VERSION 5.7 ;
BUSBITCHARS "[]" ;
DIVIDERCHAR "/" ;

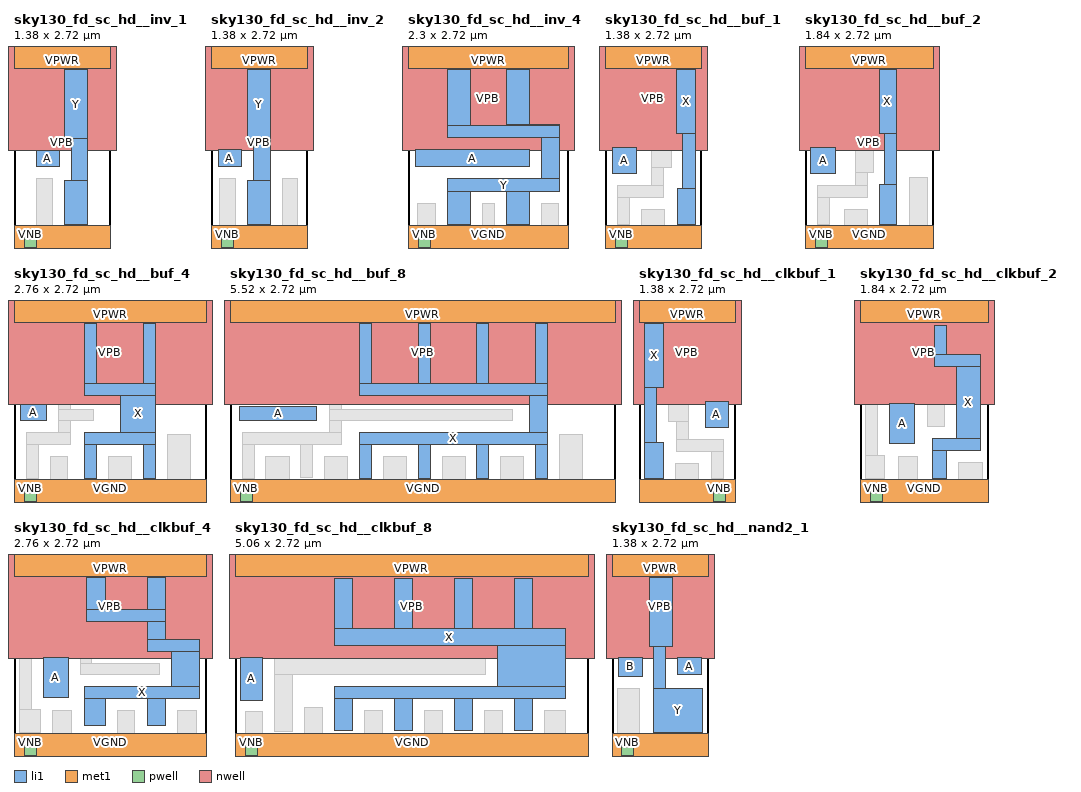
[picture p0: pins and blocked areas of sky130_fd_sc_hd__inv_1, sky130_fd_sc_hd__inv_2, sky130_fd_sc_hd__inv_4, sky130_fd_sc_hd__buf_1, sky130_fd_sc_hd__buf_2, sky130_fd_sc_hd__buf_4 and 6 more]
MACRO sky130_fd_sc_hd__inv_1
  CLASS CORE ;
  FOREIGN sky130_fd_sc_hd__inv_1 ;
  ORIGIN  0.000000  0.000000 ;
  SIZE  1.380000 BY  2.720000 ;
  SYMMETRY X Y R90 ;
  SITE unithd ;
  PIN A
    ANTENNAGATEAREA  0.247500 ;
    DIRECTION INPUT ;
    USE SIGNAL ;
    PORT
      LAYER li1 ;
        RECT 0.320000 1.075000 0.650000 1.315000 ;
    END
  END A
  PIN Y
    ANTENNADIFFAREA  0.429000 ;
    DIRECTION OUTPUT ;
    USE SIGNAL ;
    PORT
      LAYER li1 ;
        RECT 0.720000 0.255000 1.050000 0.885000 ;
        RECT 0.720000 1.485000 1.050000 2.465000 ;
        RECT 0.820000 0.885000 1.050000 1.485000 ;
    END
  END Y
  PIN VGND
    DIRECTION INOUT ;
    SHAPE ABUTMENT ;
    USE GROUND ;
    PORT
      LAYER met1 ;
        RECT 0.000000 -0.240000 1.380000 0.240000 ;
    END
  END VGND
  PIN VNB
    DIRECTION INOUT ;
    USE GROUND ;
    PORT
      LAYER pwell ;
        RECT 0.145000 -0.085000 0.315000 0.085000 ;
    END
  END VNB
  PIN VPB
    DIRECTION INOUT ;
    USE POWER ;
    PORT
      LAYER nwell ;
        RECT -0.190000 1.305000 1.570000 2.910000 ;
    END
  END VPB
  PIN VPWR
    DIRECTION INOUT ;
    SHAPE ABUTMENT ;
    USE POWER ;
    PORT
      LAYER met1 ;
        RECT 0.000000 2.480000 1.380000 2.960000 ;
    END
  END VPWR
  OBS
    LAYER li1 ;
      RECT 0.000000 -0.085000 1.380000 0.085000 ;
      RECT 0.000000  2.635000 1.380000 2.805000 ;
      RECT 0.320000  0.085000 0.550000 0.905000 ;
      RECT 0.340000  1.495000 0.550000 2.635000 ;
    LAYER mcon ;
      RECT 0.145000 -0.085000 0.315000 0.085000 ;
      RECT 0.145000  2.635000 0.315000 2.805000 ;
      RECT 0.605000 -0.085000 0.775000 0.085000 ;
      RECT 0.605000  2.635000 0.775000 2.805000 ;
      RECT 1.065000 -0.085000 1.235000 0.085000 ;
      RECT 1.065000  2.635000 1.235000 2.805000 ;
  END
END sky130_fd_sc_hd__inv_1

MACRO sky130_fd_sc_hd__inv_2
  CLASS CORE ;
  FOREIGN sky130_fd_sc_hd__inv_2 ;
  ORIGIN  0.000000  0.000000 ;
  SIZE  1.380000 BY  2.720000 ;
  SYMMETRY X Y R90 ;
  SITE unithd ;
  PIN A
    ANTENNAGATEAREA  0.495000 ;
    DIRECTION INPUT ;
    USE SIGNAL ;
    PORT
      LAYER li1 ;
        RECT 0.105000 1.075000 0.435000 1.325000 ;
    END
  END A
  PIN Y
    ANTENNADIFFAREA  0.445500 ;
    DIRECTION OUTPUT ;
    USE SIGNAL ;
    PORT
      LAYER li1 ;
        RECT 0.525000 0.255000 0.855000 0.885000 ;
        RECT 0.525000 1.485000 0.855000 2.465000 ;
        RECT 0.605000 0.885000 0.855000 1.485000 ;
    END
  END Y
  PIN VGND
    DIRECTION INOUT ;
    SHAPE ABUTMENT ;
    USE GROUND ;
    PORT
      LAYER met1 ;
        RECT 0.000000 -0.240000 1.380000 0.240000 ;
    END
  END VGND
  PIN VNB
    DIRECTION INOUT ;
    USE GROUND ;
    PORT
      LAYER pwell ;
        RECT 0.145000 -0.085000 0.315000 0.085000 ;
    END
  END VNB
  PIN VPB
    DIRECTION INOUT ;
    USE POWER ;
    PORT
      LAYER nwell ;
        RECT -0.190000 1.305000 1.570000 2.910000 ;
    END
  END VPB
  PIN VPWR
    DIRECTION INOUT ;
    SHAPE ABUTMENT ;
    USE POWER ;
    PORT
      LAYER met1 ;
        RECT 0.000000 2.480000 1.380000 2.960000 ;
    END
  END VPWR
  OBS
    LAYER li1 ;
      RECT 0.000000 -0.085000 1.380000 0.085000 ;
      RECT 0.000000  2.635000 1.380000 2.805000 ;
      RECT 0.125000  0.085000 0.355000 0.905000 ;
      RECT 0.125000  1.495000 0.355000 2.635000 ;
      RECT 1.025000  0.085000 1.235000 0.905000 ;
      RECT 1.025000  1.495000 1.235000 2.635000 ;
    LAYER mcon ;
      RECT 0.145000 -0.085000 0.315000 0.085000 ;
      RECT 0.145000  2.635000 0.315000 2.805000 ;
      RECT 0.605000 -0.085000 0.775000 0.085000 ;
      RECT 0.605000  2.635000 0.775000 2.805000 ;
      RECT 1.065000 -0.085000 1.235000 0.085000 ;
      RECT 1.065000  2.635000 1.235000 2.805000 ;
  END
END sky130_fd_sc_hd__inv_2

MACRO sky130_fd_sc_hd__inv_4
  CLASS CORE ;
  FOREIGN sky130_fd_sc_hd__inv_4 ;
  ORIGIN  0.000000  0.000000 ;
  SIZE  2.300000 BY  2.720000 ;
  SYMMETRY X Y R90 ;
  SITE unithd ;
  PIN A
    ANTENNAGATEAREA  0.990000 ;
    DIRECTION INPUT ;
    USE SIGNAL ;
    PORT
      LAYER li1 ;
        RECT 0.105000 1.075000 1.735000 1.325000 ;
    END
  END A
  PIN Y
    ANTENNADIFFAREA  0.891000 ;
    DIRECTION OUTPUT ;
    USE SIGNAL ;
    PORT
      LAYER li1 ;
        RECT 0.565000 0.255000 0.895000 0.725000 ;
        RECT 0.565000 0.725000 2.170000 0.905000 ;
        RECT 0.565000 1.495000 2.170000 1.665000 ;
        RECT 0.565000 1.665000 0.895000 2.465000 ;
        RECT 1.405000 0.255000 1.735000 0.725000 ;
        RECT 1.405000 1.665000 2.170000 1.685000 ;
        RECT 1.405000 1.685000 1.735000 2.465000 ;
        RECT 1.905000 0.905000 2.170000 1.495000 ;
    END
  END Y
  PIN VGND
    DIRECTION INOUT ;
    SHAPE ABUTMENT ;
    USE GROUND ;
    PORT
      LAYER met1 ;
        RECT 0.000000 -0.240000 2.300000 0.240000 ;
    END
  END VGND
  PIN VNB
    DIRECTION INOUT ;
    USE GROUND ;
    PORT
      LAYER pwell ;
        RECT 0.145000 -0.085000 0.315000 0.085000 ;
    END
  END VNB
  PIN VPB
    DIRECTION INOUT ;
    USE POWER ;
    PORT
      LAYER nwell ;
        RECT -0.190000 1.305000 2.490000 2.910000 ;
    END
  END VPB
  PIN VPWR
    DIRECTION INOUT ;
    SHAPE ABUTMENT ;
    USE POWER ;
    PORT
      LAYER met1 ;
        RECT 0.000000 2.480000 2.300000 2.960000 ;
    END
  END VPWR
  OBS
    LAYER li1 ;
      RECT 0.000000 -0.085000 2.300000 0.085000 ;
      RECT 0.000000  2.635000 2.300000 2.805000 ;
      RECT 0.130000  0.085000 0.395000 0.545000 ;
      RECT 0.130000  1.495000 0.395000 2.635000 ;
      RECT 1.065000  0.085000 1.235000 0.545000 ;
      RECT 1.065000  1.835000 1.235000 2.635000 ;
      RECT 1.905000  0.085000 2.155000 0.550000 ;
      RECT 1.905000  2.175000 2.115000 2.635000 ;
    LAYER mcon ;
      RECT 0.145000 -0.085000 0.315000 0.085000 ;
      RECT 0.145000  2.635000 0.315000 2.805000 ;
      RECT 0.605000 -0.085000 0.775000 0.085000 ;
      RECT 0.605000  2.635000 0.775000 2.805000 ;
      RECT 1.065000 -0.085000 1.235000 0.085000 ;
      RECT 1.065000  2.635000 1.235000 2.805000 ;
      RECT 1.525000 -0.085000 1.695000 0.085000 ;
      RECT 1.525000  2.635000 1.695000 2.805000 ;
      RECT 1.985000 -0.085000 2.155000 0.085000 ;
      RECT 1.985000  2.635000 2.155000 2.805000 ;
  END
END sky130_fd_sc_hd__inv_4

MACRO sky130_fd_sc_hd__buf_1
  CLASS CORE ;
  FOREIGN sky130_fd_sc_hd__buf_1 ;
  ORIGIN  0.000000  0.000000 ;
  SIZE  1.380000 BY  2.720000 ;
  SYMMETRY X Y R90 ;
  SITE unithd ;
  PIN A
    ANTENNAGATEAREA  0.196500 ;
    DIRECTION INPUT ;
    USE SIGNAL ;
    PORT
      LAYER li1 ;
        RECT 0.105000 0.985000 0.445000 1.355000 ;
    END
  END A
  PIN X
    ANTENNADIFFAREA  0.340600 ;
    DIRECTION OUTPUT ;
    USE SIGNAL ;
    PORT
      LAYER li1 ;
        RECT 1.025000 1.560000 1.295000 2.465000 ;
        RECT 1.035000 0.255000 1.295000 0.760000 ;
        RECT 1.115000 0.760000 1.295000 1.560000 ;
    END
  END X
  PIN VGND
    DIRECTION INOUT ;
    SHAPE ABUTMENT ;
    USE GROUND ;
    PORT
      LAYER met1 ;
        RECT 0.000000 -0.240000 1.380000 0.240000 ;
    END
  END VGND
  PIN VNB
    DIRECTION INOUT ;
    USE GROUND ;
    PORT
      LAYER pwell ;
        RECT 0.155000 -0.085000 0.325000 0.085000 ;
    END
  END VNB
  PIN VPB
    DIRECTION INOUT ;
    USE POWER ;
    PORT
      LAYER nwell ;
        RECT -0.190000 1.305000 1.570000 2.910000 ;
    END
  END VPB
  PIN VPWR
    DIRECTION INOUT ;
    SHAPE ABUTMENT ;
    USE POWER ;
    PORT
      LAYER met1 ;
        RECT 0.000000 2.480000 1.380000 2.960000 ;
    END
  END VPWR
  OBS
    LAYER li1 ;
      RECT 0.000000 -0.085000 1.380000 0.085000 ;
      RECT 0.000000  2.635000 1.380000 2.805000 ;
      RECT 0.165000  1.535000 0.840000 1.705000 ;
      RECT 0.165000  1.705000 0.345000 2.465000 ;
      RECT 0.175000  0.255000 0.345000 0.635000 ;
      RECT 0.175000  0.635000 0.840000 0.805000 ;
      RECT 0.525000  0.085000 0.855000 0.465000 ;
      RECT 0.525000  1.875000 0.855000 2.635000 ;
      RECT 0.670000  0.805000 0.840000 1.060000 ;
      RECT 0.670000  1.060000 0.945000 1.390000 ;
      RECT 0.670000  1.390000 0.840000 1.535000 ;
    LAYER mcon ;
      RECT 0.145000 -0.085000 0.315000 0.085000 ;
      RECT 0.145000  2.635000 0.315000 2.805000 ;
      RECT 0.605000 -0.085000 0.775000 0.085000 ;
      RECT 0.605000  2.635000 0.775000 2.805000 ;
      RECT 1.065000 -0.085000 1.235000 0.085000 ;
      RECT 1.065000  2.635000 1.235000 2.805000 ;
  END
END sky130_fd_sc_hd__buf_1

MACRO sky130_fd_sc_hd__buf_2
  CLASS CORE ;
  FOREIGN sky130_fd_sc_hd__buf_2 ;
  ORIGIN  0.000000  0.000000 ;
  SIZE  1.840000 BY  2.720000 ;
  SYMMETRY X Y R90 ;
  SITE unithd ;
  PIN A
    ANTENNAGATEAREA  0.159000 ;
    DIRECTION INPUT ;
    USE SIGNAL ;
    PORT
      LAYER li1 ;
        RECT 0.085000 0.985000 0.440000 1.355000 ;
    END
  END A
  PIN X
    ANTENNADIFFAREA  0.445500 ;
    DIRECTION OUTPUT ;
    USE SIGNAL ;
    PORT
      LAYER li1 ;
        RECT 1.060000 0.255000 1.315000 0.830000 ;
        RECT 1.060000 1.560000 1.315000 2.465000 ;
        RECT 1.145000 0.830000 1.315000 1.560000 ;
    END
  END X
  PIN VGND
    DIRECTION INOUT ;
    SHAPE ABUTMENT ;
    USE GROUND ;
    PORT
      LAYER met1 ;
        RECT 0.000000 -0.240000 1.840000 0.240000 ;
    END
  END VGND
  PIN VNB
    DIRECTION INOUT ;
    USE GROUND ;
    PORT
      LAYER pwell ;
        RECT 0.145000 -0.085000 0.315000 0.085000 ;
    END
  END VNB
  PIN VPB
    DIRECTION INOUT ;
    USE POWER ;
    PORT
      LAYER nwell ;
        RECT -0.190000 1.305000 2.030000 2.910000 ;
    END
  END VPB
  PIN VPWR
    DIRECTION INOUT ;
    SHAPE ABUTMENT ;
    USE POWER ;
    PORT
      LAYER met1 ;
        RECT 0.000000 2.480000 1.840000 2.960000 ;
    END
  END VPWR
  OBS
    LAYER li1 ;
      RECT 0.000000 -0.085000 1.840000 0.085000 ;
      RECT 0.000000  2.635000 1.840000 2.805000 ;
      RECT 0.175000  0.255000 0.345000 0.635000 ;
      RECT 0.175000  0.635000 0.890000 0.805000 ;
      RECT 0.175000  1.535000 0.890000 1.705000 ;
      RECT 0.175000  1.705000 0.345000 2.465000 ;
      RECT 0.560000  0.085000 0.890000 0.465000 ;
      RECT 0.560000  1.875000 0.890000 2.635000 ;
      RECT 0.720000  0.805000 0.890000 0.995000 ;
      RECT 0.720000  0.995000 0.975000 1.325000 ;
      RECT 0.720000  1.325000 0.890000 1.535000 ;
      RECT 1.490000  0.085000 1.750000 0.925000 ;
      RECT 1.490000  1.485000 1.750000 2.635000 ;
    LAYER mcon ;
      RECT 0.145000 -0.085000 0.315000 0.085000 ;
      RECT 0.145000  2.635000 0.315000 2.805000 ;
      RECT 0.605000 -0.085000 0.775000 0.085000 ;
      RECT 0.605000  2.635000 0.775000 2.805000 ;
      RECT 1.065000 -0.085000 1.235000 0.085000 ;
      RECT 1.065000  2.635000 1.235000 2.805000 ;
      RECT 1.525000 -0.085000 1.695000 0.085000 ;
      RECT 1.525000  2.635000 1.695000 2.805000 ;
  END
END sky130_fd_sc_hd__buf_2

MACRO sky130_fd_sc_hd__buf_4
  CLASS CORE ;
  FOREIGN sky130_fd_sc_hd__buf_4 ;
  ORIGIN  0.000000  0.000000 ;
  SIZE  2.760000 BY  2.720000 ;
  SYMMETRY X Y R90 ;
  SITE unithd ;
  PIN A
    ANTENNAGATEAREA  0.247500 ;
    DIRECTION INPUT ;
    USE SIGNAL ;
    PORT
      LAYER li1 ;
        RECT 0.090000 1.075000 0.470000 1.315000 ;
    END
  END A
  PIN X
    ANTENNADIFFAREA  0.891000 ;
    DIRECTION OUTPUT ;
    USE SIGNAL ;
    PORT
      LAYER li1 ;
        RECT 1.015000 0.255000 1.185000 0.735000 ;
        RECT 1.015000 0.735000 2.025000 0.905000 ;
        RECT 1.015000 1.445000 2.025000 1.615000 ;
        RECT 1.015000 1.615000 1.185000 2.465000 ;
        RECT 1.530000 0.905000 2.025000 1.445000 ;
        RECT 1.855000 0.255000 2.025000 0.735000 ;
        RECT 1.855000 1.615000 2.025000 2.465000 ;
    END
  END X
  PIN VGND
    DIRECTION INOUT ;
    SHAPE ABUTMENT ;
    USE GROUND ;
    PORT
      LAYER met1 ;
        RECT 0.000000 -0.240000 2.760000 0.240000 ;
    END
  END VGND
  PIN VNB
    DIRECTION INOUT ;
    USE GROUND ;
    PORT
      LAYER pwell ;
        RECT 0.150000 -0.085000 0.320000 0.085000 ;
    END
  END VNB
  PIN VPB
    DIRECTION INOUT ;
    USE POWER ;
    PORT
      LAYER nwell ;
        RECT -0.190000 1.305000 2.950000 2.910000 ;
    END
  END VPB
  PIN VPWR
    DIRECTION INOUT ;
    SHAPE ABUTMENT ;
    USE POWER ;
    PORT
      LAYER met1 ;
        RECT 0.000000 2.480000 2.760000 2.960000 ;
    END
  END VPWR
  OBS
    LAYER li1 ;
      RECT 0.000000 -0.085000 2.760000 0.085000 ;
      RECT 0.000000  2.635000 2.760000 2.805000 ;
      RECT 0.095000  1.485000 0.810000 1.655000 ;
      RECT 0.095000  1.655000 0.425000 2.465000 ;
      RECT 0.175000  0.255000 0.345000 0.735000 ;
      RECT 0.175000  0.735000 0.810000 0.905000 ;
      RECT 0.525000  0.085000 0.765000 0.565000 ;
      RECT 0.595000  1.835000 0.835000 2.635000 ;
      RECT 0.640000  0.905000 0.810000 1.075000 ;
      RECT 0.640000  1.075000 1.140000 1.245000 ;
      RECT 0.640000  1.245000 0.810000 1.485000 ;
      RECT 1.355000  0.085000 1.685000 0.565000 ;
      RECT 1.355000  1.835000 1.685000 2.635000 ;
      RECT 2.195000  0.085000 2.525000 0.885000 ;
      RECT 2.195000  1.485000 2.525000 2.635000 ;
    LAYER mcon ;
      RECT 0.145000 -0.085000 0.315000 0.085000 ;
      RECT 0.145000  2.635000 0.315000 2.805000 ;
      RECT 0.605000 -0.085000 0.775000 0.085000 ;
      RECT 0.605000  2.635000 0.775000 2.805000 ;
      RECT 1.065000 -0.085000 1.235000 0.085000 ;
      RECT 1.065000  2.635000 1.235000 2.805000 ;
      RECT 1.525000 -0.085000 1.695000 0.085000 ;
      RECT 1.525000  2.635000 1.695000 2.805000 ;
      RECT 1.985000 -0.085000 2.155000 0.085000 ;
      RECT 1.985000  2.635000 2.155000 2.805000 ;
      RECT 2.445000 -0.085000 2.615000 0.085000 ;
      RECT 2.445000  2.635000 2.615000 2.805000 ;
  END
END sky130_fd_sc_hd__buf_4

MACRO sky130_fd_sc_hd__buf_8
  CLASS CORE ;
  FOREIGN sky130_fd_sc_hd__buf_8 ;
  ORIGIN  0.000000  0.000000 ;
  SIZE  5.520000 BY  2.720000 ;
  SYMMETRY X Y R90 ;
  SITE unithd ;
  PIN A
    ANTENNAGATEAREA  0.742500 ;
    DIRECTION INPUT ;
    USE SIGNAL ;
    PORT
      LAYER li1 ;
        RECT 0.140000 1.075000 1.240000 1.275000 ;
    END
  END A
  PIN X
    ANTENNADIFFAREA  1.782000 ;
    DIRECTION OUTPUT ;
    USE SIGNAL ;
    PORT
      LAYER li1 ;
        RECT 1.855000 0.255000 2.025000 0.735000 ;
        RECT 1.855000 0.735000 4.545000 0.905000 ;
        RECT 1.855000 1.445000 4.545000 1.615000 ;
        RECT 1.855000 1.615000 2.025000 2.465000 ;
        RECT 2.695000 0.255000 2.865000 0.735000 ;
        RECT 2.695000 1.615000 2.865000 2.465000 ;
        RECT 3.535000 0.255000 3.705000 0.735000 ;
        RECT 3.535000 1.615000 3.705000 2.465000 ;
        RECT 4.290000 0.905000 4.545000 1.445000 ;
        RECT 4.375000 0.255000 4.545000 0.735000 ;
        RECT 4.375000 1.615000 4.545000 2.465000 ;
    END
  END X
  PIN VGND
    DIRECTION INOUT ;
    SHAPE ABUTMENT ;
    USE GROUND ;
    PORT
      LAYER met1 ;
        RECT 0.000000 -0.240000 5.520000 0.240000 ;
    END
  END VGND
  PIN VNB
    DIRECTION INOUT ;
    USE GROUND ;
    PORT
      LAYER pwell ;
        RECT 0.150000 -0.085000 0.320000 0.085000 ;
    END
  END VNB
  PIN VPB
    DIRECTION INOUT ;
    USE POWER ;
    PORT
      LAYER nwell ;
        RECT -0.190000 1.305000 5.710000 2.910000 ;
    END
  END VPB
  PIN VPWR
    DIRECTION INOUT ;
    SHAPE ABUTMENT ;
    USE POWER ;
    PORT
      LAYER met1 ;
        RECT 0.000000 2.480000 5.520000 2.960000 ;
    END
  END VPWR
  OBS
    LAYER li1 ;
      RECT 0.000000 -0.085000 5.520000 0.085000 ;
      RECT 0.000000  2.635000 5.520000 2.805000 ;
      RECT 0.095000  1.445000 1.595000 1.615000 ;
      RECT 0.095000  1.615000 0.425000 2.465000 ;
      RECT 0.175000  0.255000 0.345000 0.735000 ;
      RECT 0.175000  0.735000 1.595000 0.905000 ;
      RECT 0.515000  0.085000 0.845000 0.565000 ;
      RECT 0.595000  1.835000 0.765000 2.635000 ;
      RECT 0.935000  1.615000 1.265000 2.465000 ;
      RECT 1.015000  0.260000 1.185000 0.735000 ;
      RECT 1.355000  0.085000 1.685000 0.565000 ;
      RECT 1.420000  0.905000 1.595000 1.075000 ;
      RECT 1.420000  1.075000 4.045000 1.245000 ;
      RECT 1.420000  1.245000 1.595000 1.445000 ;
      RECT 1.435000  1.835000 1.605000 2.635000 ;
      RECT 2.195000  0.085000 2.525000 0.565000 ;
      RECT 2.195000  1.835000 2.525000 2.635000 ;
      RECT 3.035000  0.085000 3.365000 0.565000 ;
      RECT 3.035000  1.835000 3.365000 2.635000 ;
      RECT 3.875000  0.085000 4.205000 0.565000 ;
      RECT 3.875000  1.835000 4.205000 2.635000 ;
      RECT 4.715000  0.085000 5.045000 0.885000 ;
      RECT 4.715000  1.485000 5.045000 2.635000 ;
    LAYER mcon ;
      RECT 0.145000 -0.085000 0.315000 0.085000 ;
      RECT 0.145000  2.635000 0.315000 2.805000 ;
      RECT 0.605000 -0.085000 0.775000 0.085000 ;
      RECT 0.605000  2.635000 0.775000 2.805000 ;
      RECT 1.065000 -0.085000 1.235000 0.085000 ;
      RECT 1.065000  2.635000 1.235000 2.805000 ;
      RECT 1.525000 -0.085000 1.695000 0.085000 ;
      RECT 1.525000  2.635000 1.695000 2.805000 ;
      RECT 1.985000 -0.085000 2.155000 0.085000 ;
      RECT 1.985000  2.635000 2.155000 2.805000 ;
      RECT 2.445000 -0.085000 2.615000 0.085000 ;
      RECT 2.445000  2.635000 2.615000 2.805000 ;
      RECT 2.905000 -0.085000 3.075000 0.085000 ;
      RECT 2.905000  2.635000 3.075000 2.805000 ;
      RECT 3.365000 -0.085000 3.535000 0.085000 ;
      RECT 3.365000  2.635000 3.535000 2.805000 ;
      RECT 3.825000 -0.085000 3.995000 0.085000 ;
      RECT 3.825000  2.635000 3.995000 2.805000 ;
      RECT 4.285000 -0.085000 4.455000 0.085000 ;
      RECT 4.285000  2.635000 4.455000 2.805000 ;
      RECT 4.745000 -0.085000 4.915000 0.085000 ;
      RECT 4.745000  2.635000 4.915000 2.805000 ;
      RECT 5.205000 -0.085000 5.375000 0.085000 ;
      RECT 5.205000  2.635000 5.375000 2.805000 ;
  END
END sky130_fd_sc_hd__buf_8

MACRO sky130_fd_sc_hd__clkbuf_1
  CLASS CORE ;
  FOREIGN sky130_fd_sc_hd__clkbuf_1 ;
  ORIGIN  0.000000  0.000000 ;
  SIZE  1.380000 BY  2.720000 ;
  SYMMETRY X Y R90 ;
  SITE unithd ;
  PIN A
    ANTENNAGATEAREA  0.196500 ;
    DIRECTION INPUT ;
    USE SIGNAL ;
    PORT
      LAYER li1 ;
        RECT 0.945000 0.985000 1.275000 1.355000 ;
    END
  END A
  PIN X
    ANTENNADIFFAREA  0.340600 ;
    DIRECTION OUTPUT ;
    USE SIGNAL ;
    PORT
      LAYER li1 ;
        RECT 0.085000 0.255000 0.345000 0.760000 ;
        RECT 0.085000 0.760000 0.255000 1.560000 ;
        RECT 0.085000 1.560000 0.355000 2.465000 ;
    END
  END X
  PIN VGND
    DIRECTION INOUT ;
    SHAPE ABUTMENT ;
    USE GROUND ;
    PORT
      LAYER met1 ;
        RECT 0.000000 -0.240000 1.380000 0.240000 ;
    END
  END VGND
  PIN VNB
    DIRECTION INOUT ;
    USE GROUND ;
    PORT
      LAYER pwell ;
        RECT 1.065000 -0.085000 1.235000 0.085000 ;
    END
  END VNB
  PIN VPB
    DIRECTION INOUT ;
    USE POWER ;
    PORT
      LAYER nwell ;
        RECT -0.190000 1.305000 1.570000 2.910000 ;
    END
  END VPB
  PIN VPWR
    DIRECTION INOUT ;
    SHAPE ABUTMENT ;
    USE POWER ;
    PORT
      LAYER met1 ;
        RECT 0.000000 2.480000 1.380000 2.960000 ;
    END
  END VPWR
  OBS
    LAYER li1 ;
      RECT 0.000000 -0.085000 1.380000 0.085000 ;
      RECT 0.000000  2.635000 1.380000 2.805000 ;
      RECT 0.425000  1.060000 0.710000 1.390000 ;
      RECT 0.525000  0.085000 0.855000 0.465000 ;
      RECT 0.525000  1.875000 0.855000 2.635000 ;
      RECT 0.540000  0.635000 1.205000 0.805000 ;
      RECT 0.540000  0.805000 0.710000 1.060000 ;
      RECT 0.540000  1.390000 0.710000 1.535000 ;
      RECT 0.540000  1.535000 1.205000 1.705000 ;
      RECT 1.035000  0.255000 1.205000 0.635000 ;
      RECT 1.035000  1.705000 1.205000 2.465000 ;
    LAYER mcon ;
      RECT 0.145000 -0.085000 0.315000 0.085000 ;
      RECT 0.145000  2.635000 0.315000 2.805000 ;
      RECT 0.605000 -0.085000 0.775000 0.085000 ;
      RECT 0.605000  2.635000 0.775000 2.805000 ;
      RECT 1.065000 -0.085000 1.235000 0.085000 ;
      RECT 1.065000  2.635000 1.235000 2.805000 ;
  END
END sky130_fd_sc_hd__clkbuf_1

MACRO sky130_fd_sc_hd__clkbuf_2
  CLASS CORE ;
  FOREIGN sky130_fd_sc_hd__clkbuf_2 ;
  ORIGIN  0.000000  0.000000 ;
  SIZE  1.840000 BY  2.720000 ;
  SYMMETRY X Y R90 ;
  SITE unithd ;
  PIN A
    ANTENNAGATEAREA  0.213000 ;
    DIRECTION INPUT ;
    USE SIGNAL ;
    PORT
      LAYER li1 ;
        RECT 0.425000 0.745000 0.785000 1.325000 ;
    END
  END A
  PIN X
    ANTENNADIFFAREA  0.383400 ;
    DIRECTION OUTPUT ;
    USE SIGNAL ;
    PORT
      LAYER li1 ;
        RECT 1.040000 0.255000 1.245000 0.655000 ;
        RECT 1.040000 0.655000 1.725000 0.825000 ;
        RECT 1.060000 1.855000 1.725000 2.030000 ;
        RECT 1.060000 2.030000 1.245000 2.435000 ;
        RECT 1.385000 0.825000 1.725000 1.855000 ;
    END
  END X
  PIN VGND
    DIRECTION INOUT ;
    SHAPE ABUTMENT ;
    USE GROUND ;
    PORT
      LAYER met1 ;
        RECT 0.000000 -0.240000 1.840000 0.240000 ;
    END
  END VGND
  PIN VNB
    DIRECTION INOUT ;
    USE GROUND ;
    PORT
      LAYER pwell ;
        RECT 0.145000 -0.085000 0.315000 0.085000 ;
    END
  END VNB
  PIN VPB
    DIRECTION INOUT ;
    USE POWER ;
    PORT
      LAYER nwell ;
        RECT -0.190000 1.305000 2.030000 2.910000 ;
    END
  END VPB
  PIN VPWR
    DIRECTION INOUT ;
    SHAPE ABUTMENT ;
    USE POWER ;
    PORT
      LAYER met1 ;
        RECT 0.000000 2.480000 1.840000 2.960000 ;
    END
  END VPWR
  OBS
    LAYER li1 ;
      RECT 0.000000 -0.085000 1.840000 0.085000 ;
      RECT 0.000000  2.635000 1.840000 2.805000 ;
      RECT 0.085000  0.255000 0.345000 0.585000 ;
      RECT 0.085000  0.585000 0.255000 1.495000 ;
      RECT 0.085000  1.495000 1.215000 1.665000 ;
      RECT 0.085000  1.665000 0.355000 2.435000 ;
      RECT 0.525000  1.855000 0.855000 2.635000 ;
      RECT 0.555000  0.085000 0.830000 0.565000 ;
      RECT 0.965000  0.995000 1.215000 1.495000 ;
      RECT 1.415000  0.085000 1.750000 0.485000 ;
      RECT 1.415000  2.210000 1.750000 2.635000 ;
    LAYER mcon ;
      RECT 0.145000 -0.085000 0.315000 0.085000 ;
      RECT 0.145000  2.635000 0.315000 2.805000 ;
      RECT 0.605000 -0.085000 0.775000 0.085000 ;
      RECT 0.605000  2.635000 0.775000 2.805000 ;
      RECT 1.065000 -0.085000 1.235000 0.085000 ;
      RECT 1.065000  2.635000 1.235000 2.805000 ;
      RECT 1.525000 -0.085000 1.695000 0.085000 ;
      RECT 1.525000  2.635000 1.695000 2.805000 ;
  END
END sky130_fd_sc_hd__clkbuf_2

MACRO sky130_fd_sc_hd__clkbuf_4
  CLASS CORE ;
  FOREIGN sky130_fd_sc_hd__clkbuf_4 ;
  ORIGIN  0.000000  0.000000 ;
  SIZE  2.760000 BY  2.720000 ;
  SYMMETRY X Y R90 ;
  SITE unithd ;
  PIN A
    ANTENNAGATEAREA  0.213000 ;
    DIRECTION INPUT ;
    USE SIGNAL ;
    PORT
      LAYER li1 ;
        RECT 0.425000 0.755000 0.775000 1.325000 ;
    END
  END A
  PIN X
    ANTENNADIFFAREA  0.795200 ;
    DIRECTION OUTPUT ;
    USE SIGNAL ;
    PORT
      LAYER li1 ;
        RECT 1.010000 0.345000 1.305000 0.735000 ;
        RECT 1.010000 0.735000 2.660000 0.905000 ;
        RECT 1.045000 1.835000 2.165000 2.005000 ;
        RECT 1.045000 2.005000 1.305000 2.465000 ;
        RECT 1.905000 0.345000 2.165000 0.735000 ;
        RECT 1.905000 1.415000 2.660000 1.585000 ;
        RECT 1.905000 1.585000 2.165000 1.835000 ;
        RECT 1.905000 2.005000 2.165000 2.465000 ;
        RECT 2.255000 0.905000 2.660000 1.415000 ;
    END
  END X
  PIN VGND
    DIRECTION INOUT ;
    SHAPE ABUTMENT ;
    USE GROUND ;
    PORT
      LAYER met1 ;
        RECT 0.000000 -0.240000 2.760000 0.240000 ;
    END
  END VGND
  PIN VNB
    DIRECTION INOUT ;
    USE GROUND ;
    PORT
      LAYER pwell ;
        RECT 0.145000 -0.085000 0.315000 0.085000 ;
    END
  END VNB
  PIN VPB
    DIRECTION INOUT ;
    USE POWER ;
    PORT
      LAYER nwell ;
        RECT -0.190000 1.305000 2.950000 2.910000 ;
    END
  END VPB
  PIN VPWR
    DIRECTION INOUT ;
    SHAPE ABUTMENT ;
    USE POWER ;
    PORT
      LAYER met1 ;
        RECT 0.000000 2.480000 2.760000 2.960000 ;
    END
  END VPWR
  OBS
    LAYER li1 ;
      RECT 0.000000 -0.085000 2.760000 0.085000 ;
      RECT 0.000000  2.635000 2.760000 2.805000 ;
      RECT 0.085000  0.255000 0.385000 0.585000 ;
      RECT 0.085000  0.585000 0.255000 1.495000 ;
      RECT 0.085000  1.495000 1.115000 1.665000 ;
      RECT 0.085000  1.665000 0.395000 2.465000 ;
      RECT 0.555000  0.085000 0.830000 0.565000 ;
      RECT 0.565000  1.835000 0.875000 2.635000 ;
      RECT 0.945000  1.075000 2.085000 1.245000 ;
      RECT 0.945000  1.245000 1.115000 1.495000 ;
      RECT 1.475000  0.085000 1.730000 0.565000 ;
      RECT 1.475000  2.175000 1.730000 2.635000 ;
      RECT 2.335000  0.085000 2.615000 0.565000 ;
      RECT 2.335000  1.765000 2.620000 2.635000 ;
    LAYER mcon ;
      RECT 0.145000 -0.085000 0.315000 0.085000 ;
      RECT 0.145000  2.635000 0.315000 2.805000 ;
      RECT 0.605000 -0.085000 0.775000 0.085000 ;
      RECT 0.605000  2.635000 0.775000 2.805000 ;
      RECT 1.065000 -0.085000 1.235000 0.085000 ;
      RECT 1.065000  2.635000 1.235000 2.805000 ;
      RECT 1.525000 -0.085000 1.695000 0.085000 ;
      RECT 1.525000  2.635000 1.695000 2.805000 ;
      RECT 1.985000 -0.085000 2.155000 0.085000 ;
      RECT 1.985000  2.635000 2.155000 2.805000 ;
      RECT 2.445000 -0.085000 2.615000 0.085000 ;
      RECT 2.445000  2.635000 2.615000 2.805000 ;
  END
END sky130_fd_sc_hd__clkbuf_4

MACRO sky130_fd_sc_hd__clkbuf_8
  CLASS CORE ;
  FOREIGN sky130_fd_sc_hd__clkbuf_8 ;
  ORIGIN  0.000000  0.000000 ;
  SIZE  5.060000 BY  2.720000 ;
  SYMMETRY X Y R90 ;
  SITE unithd ;
  PIN A
    ANTENNAGATEAREA  0.426000 ;
    DIRECTION INPUT ;
    USE SIGNAL ;
    PORT
      LAYER li1 ;
        RECT 0.085000 0.715000 0.400000 1.325000 ;
    END
  END A
  PIN X
    ANTENNADIFFAREA  1.590400 ;
    DIRECTION OUTPUT ;
    USE SIGNAL ;
    PORT
      LAYER li1 ;
        RECT 1.420000 0.280000 1.680000 0.735000 ;
        RECT 1.420000 0.735000 4.730000 0.905000 ;
        RECT 1.420000 1.495000 4.730000 1.735000 ;
        RECT 1.420000 1.735000 1.680000 2.460000 ;
        RECT 2.280000 0.280000 2.540000 0.735000 ;
        RECT 2.280000 1.735000 2.540000 2.460000 ;
        RECT 3.140000 0.280000 3.400000 0.735000 ;
        RECT 3.140000 1.735000 3.400000 2.460000 ;
        RECT 3.760000 0.905000 4.730000 1.495000 ;
        RECT 4.000000 0.280000 4.260000 0.735000 ;
        RECT 4.000000 1.735000 4.260000 2.460000 ;
    END
  END X
  PIN VGND
    DIRECTION INOUT ;
    SHAPE ABUTMENT ;
    USE GROUND ;
    PORT
      LAYER met1 ;
        RECT 0.000000 -0.240000 5.060000 0.240000 ;
    END
  END VGND
  PIN VNB
    DIRECTION INOUT ;
    USE GROUND ;
    PORT
      LAYER pwell ;
        RECT 0.145000 -0.085000 0.315000 0.085000 ;
    END
  END VNB
  PIN VPB
    DIRECTION INOUT ;
    USE POWER ;
    PORT
      LAYER nwell ;
        RECT -0.190000 1.305000 5.250000 2.910000 ;
    END
  END VPB
  PIN VPWR
    DIRECTION INOUT ;
    SHAPE ABUTMENT ;
    USE POWER ;
    PORT
      LAYER met1 ;
        RECT 0.000000 2.480000 5.060000 2.960000 ;
    END
  END VPWR
  OBS
    LAYER li1 ;
      RECT 0.000000 -0.085000 5.060000 0.085000 ;
      RECT 0.000000  2.635000 5.060000 2.805000 ;
      RECT 0.095000  1.525000 0.390000 2.635000 ;
      RECT 0.145000  0.085000 0.390000 0.545000 ;
      RECT 0.570000  0.265000 0.820000 1.075000 ;
      RECT 0.570000  1.075000 3.590000 1.325000 ;
      RECT 0.570000  1.325000 0.820000 2.460000 ;
      RECT 0.990000  0.085000 1.250000 0.610000 ;
      RECT 0.990000  1.525000 1.250000 2.635000 ;
      RECT 1.850000  0.085000 2.110000 0.565000 ;
      RECT 1.850000  1.905000 2.110000 2.635000 ;
      RECT 2.710000  0.085000 2.970000 0.565000 ;
      RECT 2.710000  1.905000 2.970000 2.635000 ;
      RECT 3.570000  0.085000 3.830000 0.565000 ;
      RECT 3.570000  1.905000 3.830000 2.635000 ;
      RECT 4.430000  0.085000 4.730000 0.565000 ;
      RECT 4.430000  1.905000 4.725000 2.635000 ;
    LAYER mcon ;
      RECT 0.145000 -0.085000 0.315000 0.085000 ;
      RECT 0.145000  2.635000 0.315000 2.805000 ;
      RECT 0.605000 -0.085000 0.775000 0.085000 ;
      RECT 0.605000  2.635000 0.775000 2.805000 ;
      RECT 1.065000 -0.085000 1.235000 0.085000 ;
      RECT 1.065000  2.635000 1.235000 2.805000 ;
      RECT 1.525000 -0.085000 1.695000 0.085000 ;
      RECT 1.525000  2.635000 1.695000 2.805000 ;
      RECT 1.985000 -0.085000 2.155000 0.085000 ;
      RECT 1.985000  2.635000 2.155000 2.805000 ;
      RECT 2.445000 -0.085000 2.615000 0.085000 ;
      RECT 2.445000  2.635000 2.615000 2.805000 ;
      RECT 2.905000 -0.085000 3.075000 0.085000 ;
      RECT 2.905000  2.635000 3.075000 2.805000 ;
      RECT 3.365000 -0.085000 3.535000 0.085000 ;
      RECT 3.365000  2.635000 3.535000 2.805000 ;
      RECT 3.825000 -0.085000 3.995000 0.085000 ;
      RECT 3.825000  2.635000 3.995000 2.805000 ;
      RECT 4.285000 -0.085000 4.455000 0.085000 ;
      RECT 4.285000  2.635000 4.455000 2.805000 ;
      RECT 4.745000 -0.085000 4.915000 0.085000 ;
      RECT 4.745000  2.635000 4.915000 2.805000 ;
  END
END sky130_fd_sc_hd__clkbuf_8

MACRO sky130_fd_sc_hd__nand2_1
  CLASS CORE ;
  FOREIGN sky130_fd_sc_hd__nand2_1 ;
  ORIGIN  0.000000  0.000000 ;
  SIZE  1.380000 BY  2.720000 ;
  SYMMETRY X Y R90 ;
  SITE unithd ;
  PIN A
    ANTENNAGATEAREA  0.247500 ;
    DIRECTION INPUT ;
    USE SIGNAL ;
    PORT
      LAYER li1 ;
        RECT 0.940000 1.075000 1.275000 1.325000 ;
    END
  END A
  PIN B
    ANTENNAGATEAREA  0.247500 ;
    DIRECTION INPUT ;
    USE SIGNAL ;
    PORT
      LAYER li1 ;
        RECT 0.095000 1.055000 0.430000 1.325000 ;
    END
  END B
  PIN Y
    ANTENNADIFFAREA  0.439000 ;
    DIRECTION OUTPUT ;
    USE SIGNAL ;
    PORT
      LAYER li1 ;
        RECT 0.535000 1.485000 0.865000 2.465000 ;
        RECT 0.600000 0.255000 1.295000 0.885000 ;
        RECT 0.600000 0.885000 0.770000 1.485000 ;
    END
  END Y
  PIN VGND
    DIRECTION INOUT ;
    SHAPE ABUTMENT ;
    USE GROUND ;
    PORT
      LAYER met1 ;
        RECT 0.000000 -0.240000 1.380000 0.240000 ;
    END
  END VGND
  PIN VNB
    DIRECTION INOUT ;
    USE GROUND ;
    PORT
      LAYER pwell ;
        RECT 0.140000 -0.085000 0.310000 0.085000 ;
    END
  END VNB
  PIN VPB
    DIRECTION INOUT ;
    USE POWER ;
    PORT
      LAYER nwell ;
        RECT -0.190000 1.305000 1.570000 2.910000 ;
    END
  END VPB
  PIN VPWR
    DIRECTION INOUT ;
    SHAPE ABUTMENT ;
    USE POWER ;
    PORT
      LAYER met1 ;
        RECT 0.000000 2.480000 1.380000 2.960000 ;
    END
  END VPWR
  OBS
    LAYER li1 ;
      RECT 0.000000 -0.085000 1.380000 0.085000 ;
      RECT 0.000000  2.635000 1.380000 2.805000 ;
      RECT 0.085000  0.085000 0.395000 0.885000 ;
      RECT 0.085000  1.495000 0.365000 2.635000 ;
      RECT 1.035000  1.495000 1.295000 2.635000 ;
    LAYER mcon ;
      RECT 0.145000 -0.085000 0.315000 0.085000 ;
      RECT 0.145000  2.635000 0.315000 2.805000 ;
      RECT 0.605000 -0.085000 0.775000 0.085000 ;
      RECT 0.605000  2.635000 0.775000 2.805000 ;
      RECT 1.065000 -0.085000 1.235000 0.085000 ;
      RECT 1.065000  2.635000 1.235000 2.805000 ;
  END
END sky130_fd_sc_hd__nand2_1

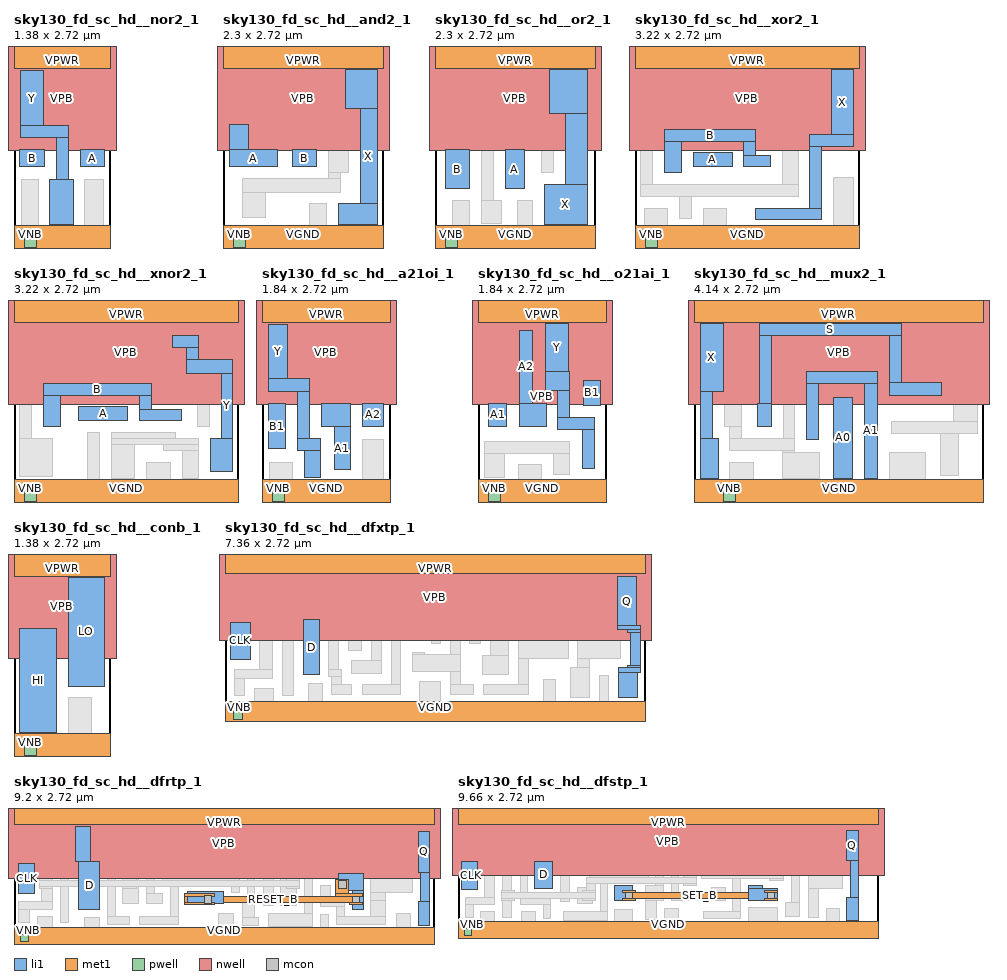
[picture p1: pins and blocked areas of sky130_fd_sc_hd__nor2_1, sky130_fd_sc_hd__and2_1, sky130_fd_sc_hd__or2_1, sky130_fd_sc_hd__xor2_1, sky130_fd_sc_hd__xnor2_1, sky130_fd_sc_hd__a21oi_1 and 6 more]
MACRO sky130_fd_sc_hd__nor2_1
  CLASS CORE ;
  FOREIGN sky130_fd_sc_hd__nor2_1 ;
  ORIGIN  0.000000  0.000000 ;
  SIZE  1.380000 BY  2.720000 ;
  SYMMETRY X Y R90 ;
  SITE unithd ;
  PIN A
    ANTENNAGATEAREA  0.247500 ;
    DIRECTION INPUT ;
    USE SIGNAL ;
    PORT
      LAYER li1 ;
        RECT 0.945000 1.075000 1.295000 1.325000 ;
    END
  END A
  PIN B
    ANTENNAGATEAREA  0.247500 ;
    DIRECTION INPUT ;
    USE SIGNAL ;
    PORT
      LAYER li1 ;
        RECT 0.085000 1.075000 0.435000 1.325000 ;
    END
  END B
  PIN Y
    ANTENNADIFFAREA  0.435500 ;
    DIRECTION OUTPUT ;
    USE SIGNAL ;
    PORT
      LAYER li1 ;
        RECT 0.095000 1.495000 0.775000 1.665000 ;
        RECT 0.095000 1.665000 0.425000 2.450000 ;
        RECT 0.515000 0.255000 0.845000 0.895000 ;
        RECT 0.605000 0.895000 0.775000 1.495000 ;
    END
  END Y
  PIN VGND
    DIRECTION INOUT ;
    SHAPE ABUTMENT ;
    USE GROUND ;
    PORT
      LAYER met1 ;
        RECT 0.000000 -0.240000 1.380000 0.240000 ;
    END
  END VGND
  PIN VNB
    DIRECTION INOUT ;
    USE GROUND ;
    PORT
      LAYER pwell ;
        RECT 0.150000 -0.085000 0.320000 0.085000 ;
    END
  END VNB
  PIN VPB
    DIRECTION INOUT ;
    USE POWER ;
    PORT
      LAYER nwell ;
        RECT -0.190000 1.305000 1.570000 2.910000 ;
    END
  END VPB
  PIN VPWR
    DIRECTION INOUT ;
    SHAPE ABUTMENT ;
    USE POWER ;
    PORT
      LAYER met1 ;
        RECT 0.000000 2.480000 1.380000 2.960000 ;
    END
  END VPWR
  OBS
    LAYER li1 ;
      RECT 0.000000 -0.085000 1.380000 0.085000 ;
      RECT 0.000000  2.635000 1.380000 2.805000 ;
      RECT 0.105000  0.085000 0.345000 0.895000 ;
      RECT 0.955000  1.495000 1.285000 2.635000 ;
      RECT 1.015000  0.085000 1.285000 0.895000 ;
    LAYER mcon ;
      RECT 0.145000 -0.085000 0.315000 0.085000 ;
      RECT 0.145000  2.635000 0.315000 2.805000 ;
      RECT 0.605000 -0.085000 0.775000 0.085000 ;
      RECT 0.605000  2.635000 0.775000 2.805000 ;
      RECT 1.065000 -0.085000 1.235000 0.085000 ;
      RECT 1.065000  2.635000 1.235000 2.805000 ;
  END
END sky130_fd_sc_hd__nor2_1

MACRO sky130_fd_sc_hd__and2_1
  CLASS CORE ;
  FOREIGN sky130_fd_sc_hd__and2_1 ;
  ORIGIN  0.000000  0.000000 ;
  SIZE  2.300000 BY  2.720000 ;
  SYMMETRY X Y R90 ;
  SITE unithd ;
  PIN A
    ANTENNAGATEAREA  0.126000 ;
    DIRECTION INPUT ;
    USE SIGNAL ;
    PORT
      LAYER li1 ;
        RECT 0.100000 1.075000 0.775000 1.325000 ;
        RECT 0.100000 1.325000 0.365000 1.685000 ;
    END
  END A
  PIN B
    ANTENNAGATEAREA  0.126000 ;
    DIRECTION INPUT ;
    USE SIGNAL ;
    PORT
      LAYER li1 ;
        RECT 0.995000 1.075000 1.335000 1.325000 ;
    END
  END B
  PIN X
    ANTENNADIFFAREA  0.657000 ;
    DIRECTION OUTPUT ;
    USE SIGNAL ;
    PORT
      LAYER li1 ;
        RECT 1.655000 0.255000 2.215000 0.545000 ;
        RECT 1.755000 1.915000 2.215000 2.465000 ;
        RECT 1.965000 0.545000 2.215000 1.915000 ;
    END
  END X
  PIN VGND
    DIRECTION INOUT ;
    SHAPE ABUTMENT ;
    USE GROUND ;
    PORT
      LAYER met1 ;
        RECT 0.000000 -0.240000 2.300000 0.240000 ;
    END
  END VGND
  PIN VNB
    DIRECTION INOUT ;
    USE GROUND ;
    PORT
      LAYER pwell ;
        RECT 0.145000 -0.085000 0.315000 0.085000 ;
    END
  END VNB
  PIN VPB
    DIRECTION INOUT ;
    USE POWER ;
    PORT
      LAYER nwell ;
        RECT -0.190000 1.305000 2.490000 2.910000 ;
    END
  END VPB
  PIN VPWR
    DIRECTION INOUT ;
    SHAPE ABUTMENT ;
    USE POWER ;
    PORT
      LAYER met1 ;
        RECT 0.000000 2.480000 2.300000 2.960000 ;
    END
  END VPWR
  OBS
    LAYER li1 ;
      RECT 0.000000 -0.085000 2.300000 0.085000 ;
      RECT 0.000000  2.635000 2.300000 2.805000 ;
      RECT 0.285000  0.355000 0.615000 0.715000 ;
      RECT 0.285000  0.715000 1.675000 0.905000 ;
      RECT 0.285000  1.965000 0.565000 2.635000 ;
      RECT 0.735000  1.575000 1.675000 1.745000 ;
      RECT 0.735000  1.745000 1.035000 2.295000 ;
      RECT 1.235000  0.085000 1.485000 0.545000 ;
      RECT 1.235000  1.915000 1.565000 2.635000 ;
      RECT 1.505000  0.905000 1.675000 0.995000 ;
      RECT 1.505000  0.995000 1.795000 1.325000 ;
      RECT 1.505000  1.325000 1.675000 1.575000 ;
    LAYER mcon ;
      RECT 0.145000 -0.085000 0.315000 0.085000 ;
      RECT 0.145000  2.635000 0.315000 2.805000 ;
      RECT 0.605000 -0.085000 0.775000 0.085000 ;
      RECT 0.605000  2.635000 0.775000 2.805000 ;
      RECT 1.065000 -0.085000 1.235000 0.085000 ;
      RECT 1.065000  2.635000 1.235000 2.805000 ;
      RECT 1.525000 -0.085000 1.695000 0.085000 ;
      RECT 1.525000  2.635000 1.695000 2.805000 ;
      RECT 1.985000 -0.085000 2.155000 0.085000 ;
      RECT 1.985000  2.635000 2.155000 2.805000 ;
  END
END sky130_fd_sc_hd__and2_1

MACRO sky130_fd_sc_hd__or2_1
  CLASS CORE ;
  FOREIGN sky130_fd_sc_hd__or2_1 ;
  ORIGIN  0.000000  0.000000 ;
  SIZE  2.300000 BY  2.720000 ;
  SYMMETRY X Y R90 ;
  SITE unithd ;
  PIN A
    ANTENNAGATEAREA  0.126000 ;
    DIRECTION INPUT ;
    USE SIGNAL ;
    PORT
      LAYER li1 ;
        RECT 1.010000 0.765000 1.275000 1.325000 ;
    END
  END A
  PIN B
    ANTENNAGATEAREA  0.126000 ;
    DIRECTION INPUT ;
    USE SIGNAL ;
    PORT
      LAYER li1 ;
        RECT 0.145000 0.765000 0.500000 1.325000 ;
    END
  END B
  PIN X
    ANTENNADIFFAREA  0.509000 ;
    DIRECTION OUTPUT ;
    USE SIGNAL ;
    PORT
      LAYER li1 ;
        RECT 1.565000 0.255000 2.180000 0.825000 ;
        RECT 1.645000 1.845000 2.180000 2.465000 ;
        RECT 1.865000 0.825000 2.180000 1.845000 ;
    END
  END X
  PIN VGND
    DIRECTION INOUT ;
    SHAPE ABUTMENT ;
    USE GROUND ;
    PORT
      LAYER met1 ;
        RECT 0.000000 -0.240000 2.300000 0.240000 ;
    END
  END VGND
  PIN VNB
    DIRECTION INOUT ;
    USE GROUND ;
    PORT
      LAYER pwell ;
        RECT 0.145000 -0.085000 0.315000 0.085000 ;
    END
  END VNB
  PIN VPB
    DIRECTION INOUT ;
    USE POWER ;
    PORT
      LAYER nwell ;
        RECT -0.190000 1.305000 2.490000 2.910000 ;
    END
  END VPB
  PIN VPWR
    DIRECTION INOUT ;
    SHAPE ABUTMENT ;
    USE POWER ;
    PORT
      LAYER met1 ;
        RECT 0.000000 2.480000 2.300000 2.960000 ;
    END
  END VPWR
  OBS
    LAYER li1 ;
      RECT 0.000000 -0.085000 2.300000 0.085000 ;
      RECT 0.000000  2.635000 2.300000 2.805000 ;
      RECT 0.250000  0.085000 0.490000 0.595000 ;
      RECT 0.270000  1.495000 1.695000 1.665000 ;
      RECT 0.270000  1.665000 0.660000 1.840000 ;
      RECT 0.670000  0.265000 0.950000 0.595000 ;
      RECT 0.670000  0.595000 0.840000 1.495000 ;
      RECT 1.145000  1.835000 1.475000 2.635000 ;
      RECT 1.180000  0.085000 1.395000 0.595000 ;
      RECT 1.525000  0.995000 1.695000 1.495000 ;
    LAYER mcon ;
      RECT 0.145000 -0.085000 0.315000 0.085000 ;
      RECT 0.145000  2.635000 0.315000 2.805000 ;
      RECT 0.605000 -0.085000 0.775000 0.085000 ;
      RECT 0.605000  2.635000 0.775000 2.805000 ;
      RECT 1.065000 -0.085000 1.235000 0.085000 ;
      RECT 1.065000  2.635000 1.235000 2.805000 ;
      RECT 1.525000 -0.085000 1.695000 0.085000 ;
      RECT 1.525000  2.635000 1.695000 2.805000 ;
      RECT 1.985000 -0.085000 2.155000 0.085000 ;
      RECT 1.985000  2.635000 2.155000 2.805000 ;
  END
END sky130_fd_sc_hd__or2_1

MACRO sky130_fd_sc_hd__xor2_1
  CLASS CORE ;
  FOREIGN sky130_fd_sc_hd__xor2_1 ;
  ORIGIN  0.000000  0.000000 ;
  SIZE  3.220000 BY  2.720000 ;
  SYMMETRY X Y R90 ;
  SITE unithd ;
  PIN A
    ANTENNAGATEAREA  0.495000 ;
    DIRECTION INPUT ;
    USE SIGNAL ;
    PORT
      LAYER li1 ;
        RECT 0.840000 1.075000 1.390000 1.275000 ;
    END
  END A
  PIN B
    ANTENNAGATEAREA  0.495000 ;
    DIRECTION INPUT ;
    USE SIGNAL ;
    PORT
      LAYER li1 ;
        RECT 0.425000 0.995000 0.670000 1.445000 ;
        RECT 0.425000 1.445000 1.730000 1.615000 ;
        RECT 1.560000 1.075000 1.935000 1.245000 ;
        RECT 1.560000 1.245000 1.730000 1.445000 ;
    END
  END B
  PIN X
    ANTENNADIFFAREA  0.800500 ;
    DIRECTION OUTPUT ;
    USE SIGNAL ;
    PORT
      LAYER li1 ;
        RECT 1.720000 0.315000 2.675000 0.485000 ;
        RECT 2.505000 0.485000 2.675000 1.365000 ;
        RECT 2.505000 1.365000 3.135000 1.535000 ;
        RECT 2.815000 1.535000 3.135000 2.465000 ;
    END
  END X
  PIN VGND
    DIRECTION INOUT ;
    SHAPE ABUTMENT ;
    USE GROUND ;
    PORT
      LAYER met1 ;
        RECT 0.000000 -0.240000 3.220000 0.240000 ;
    END
  END VGND
  PIN VNB
    DIRECTION INOUT ;
    USE GROUND ;
    PORT
      LAYER pwell ;
        RECT 0.145000 -0.085000 0.315000 0.085000 ;
    END
  END VNB
  PIN VPB
    DIRECTION INOUT ;
    USE POWER ;
    PORT
      LAYER nwell ;
        RECT -0.190000 1.305000 3.410000 2.910000 ;
    END
  END VPB
  PIN VPWR
    DIRECTION INOUT ;
    SHAPE ABUTMENT ;
    USE POWER ;
    PORT
      LAYER met1 ;
        RECT 0.000000 2.480000 3.220000 2.960000 ;
    END
  END VPWR
  OBS
    LAYER li1 ;
      RECT 0.000000 -0.085000 3.220000 0.085000 ;
      RECT 0.000000  2.635000 3.220000 2.805000 ;
      RECT 0.085000  0.655000 2.335000 0.825000 ;
      RECT 0.085000  0.825000 0.255000 1.785000 ;
      RECT 0.085000  1.785000 0.465000 2.465000 ;
      RECT 0.135000  0.085000 0.465000 0.475000 ;
      RECT 0.635000  0.335000 0.805000 0.655000 ;
      RECT 0.975000  0.085000 1.305000 0.475000 ;
      RECT 1.055000  1.785000 1.225000 2.635000 ;
      RECT 1.395000  1.785000 2.635000 1.955000 ;
      RECT 1.395000  1.955000 1.725000 2.465000 ;
      RECT 1.895000  2.125000 2.065000 2.635000 ;
      RECT 2.105000  0.825000 2.335000 1.325000 ;
      RECT 2.235000  1.955000 2.635000 2.465000 ;
      RECT 2.845000  0.085000 3.135000 0.920000 ;
    LAYER mcon ;
      RECT 0.145000 -0.085000 0.315000 0.085000 ;
      RECT 0.145000  2.635000 0.315000 2.805000 ;
      RECT 0.605000 -0.085000 0.775000 0.085000 ;
      RECT 0.605000  2.635000 0.775000 2.805000 ;
      RECT 1.065000 -0.085000 1.235000 0.085000 ;
      RECT 1.065000  2.635000 1.235000 2.805000 ;
      RECT 1.525000 -0.085000 1.695000 0.085000 ;
      RECT 1.525000  2.635000 1.695000 2.805000 ;
      RECT 1.985000 -0.085000 2.155000 0.085000 ;
      RECT 1.985000  2.635000 2.155000 2.805000 ;
      RECT 2.445000 -0.085000 2.615000 0.085000 ;
      RECT 2.445000  2.635000 2.615000 2.805000 ;
      RECT 2.905000 -0.085000 3.075000 0.085000 ;
      RECT 2.905000  2.635000 3.075000 2.805000 ;
  END
END sky130_fd_sc_hd__xor2_1

MACRO sky130_fd_sc_hd__xnor2_1
  CLASS CORE ;
  FOREIGN sky130_fd_sc_hd__xnor2_1 ;
  ORIGIN  0.000000  0.000000 ;
  SIZE  3.220000 BY  2.720000 ;
  SYMMETRY X Y R90 ;
  SITE unithd ;
  PIN A
    ANTENNAGATEAREA  0.495000 ;
    DIRECTION INPUT ;
    USE SIGNAL ;
    PORT
      LAYER li1 ;
        RECT 0.930000 1.075000 1.625000 1.275000 ;
    END
  END A
  PIN B
    ANTENNAGATEAREA  0.495000 ;
    DIRECTION INPUT ;
    USE SIGNAL ;
    PORT
      LAYER li1 ;
        RECT 0.425000 0.995000 0.670000 1.445000 ;
        RECT 0.425000 1.445000 1.965000 1.615000 ;
        RECT 1.795000 1.075000 2.395000 1.245000 ;
        RECT 1.795000 1.245000 1.965000 1.445000 ;
    END
  END B
  PIN Y
    ANTENNADIFFAREA  0.525000 ;
    DIRECTION OUTPUT ;
    USE SIGNAL ;
    PORT
      LAYER li1 ;
        RECT 2.265000 2.125000 2.645000 2.295000 ;
        RECT 2.475000 1.755000 3.135000 1.955000 ;
        RECT 2.475000 1.955000 2.645000 2.125000 ;
        RECT 2.815000 0.345000 3.135000 0.825000 ;
        RECT 2.965000 0.825000 3.135000 1.755000 ;
    END
  END Y
  PIN VGND
    DIRECTION INOUT ;
    SHAPE ABUTMENT ;
    USE GROUND ;
    PORT
      LAYER met1 ;
        RECT 0.000000 -0.240000 3.220000 0.240000 ;
    END
  END VGND
  PIN VNB
    DIRECTION INOUT ;
    USE GROUND ;
    PORT
      LAYER pwell ;
        RECT 0.145000 -0.085000 0.315000 0.085000 ;
    END
  END VNB
  PIN VPB
    DIRECTION INOUT ;
    USE POWER ;
    PORT
      LAYER nwell ;
        RECT -0.190000 1.305000 3.410000 2.910000 ;
    END
  END VPB
  PIN VPWR
    DIRECTION INOUT ;
    SHAPE ABUTMENT ;
    USE POWER ;
    PORT
      LAYER met1 ;
        RECT 0.000000 2.480000 3.220000 2.960000 ;
    END
  END VPWR
  OBS
    LAYER li1 ;
      RECT 0.000000 -0.085000 3.220000 0.085000 ;
      RECT 0.000000  2.635000 3.220000 2.805000 ;
      RECT 0.085000  0.280000 0.550000 0.825000 ;
      RECT 0.085000  0.825000 0.255000 1.785000 ;
      RECT 0.085000  1.785000 2.305000 1.955000 ;
      RECT 0.085000  2.125000 0.385000 2.635000 ;
      RECT 0.555000  1.955000 0.885000 2.465000 ;
      RECT 1.055000  0.085000 1.225000 0.905000 ;
      RECT 1.055000  2.125000 1.685000 2.635000 ;
      RECT 1.395000  0.255000 1.725000 0.735000 ;
      RECT 1.395000  0.735000 2.645000 0.825000 ;
      RECT 1.395000  0.825000 2.305000 0.905000 ;
      RECT 1.895000  0.085000 2.245000 0.475000 ;
      RECT 2.135000  0.655000 2.645000 0.735000 ;
      RECT 2.135000  1.415000 2.795000 1.585000 ;
      RECT 2.135000  1.585000 2.305000 1.785000 ;
      RECT 2.415000  0.255000 2.645000 0.655000 ;
      RECT 2.625000  0.995000 2.795000 1.415000 ;
      RECT 2.815000  2.125000 3.115000 2.635000 ;
    LAYER mcon ;
      RECT 0.145000 -0.085000 0.315000 0.085000 ;
      RECT 0.145000  2.635000 0.315000 2.805000 ;
      RECT 0.605000 -0.085000 0.775000 0.085000 ;
      RECT 0.605000  2.635000 0.775000 2.805000 ;
      RECT 1.065000 -0.085000 1.235000 0.085000 ;
      RECT 1.065000  2.635000 1.235000 2.805000 ;
      RECT 1.525000 -0.085000 1.695000 0.085000 ;
      RECT 1.525000  2.635000 1.695000 2.805000 ;
      RECT 1.985000 -0.085000 2.155000 0.085000 ;
      RECT 1.985000  2.635000 2.155000 2.805000 ;
      RECT 2.445000 -0.085000 2.615000 0.085000 ;
      RECT 2.445000  2.635000 2.615000 2.805000 ;
      RECT 2.905000 -0.085000 3.075000 0.085000 ;
      RECT 2.905000  2.635000 3.075000 2.805000 ;
  END
END sky130_fd_sc_hd__xnor2_1

MACRO sky130_fd_sc_hd__a21oi_1
  CLASS CORE ;
  FOREIGN sky130_fd_sc_hd__a21oi_1 ;
  ORIGIN  0.000000  0.000000 ;
  SIZE  1.840000 BY  2.720000 ;
  SYMMETRY X Y R90 ;
  SITE unithd ;
  PIN A1
    ANTENNAGATEAREA  0.247500 ;
    DIRECTION INPUT ;
    USE SIGNAL ;
    PORT
      LAYER li1 ;
        RECT 0.850000 0.995000 1.265000 1.325000 ;
        RECT 1.035000 0.375000 1.265000 0.995000 ;
    END
  END A1
  PIN A2
    ANTENNAGATEAREA  0.247500 ;
    DIRECTION INPUT ;
    USE SIGNAL ;
    PORT
      LAYER li1 ;
        RECT 1.445000 0.995000 1.740000 1.325000 ;
    END
  END A2
  PIN B1
    ANTENNAGATEAREA  0.247500 ;
    DIRECTION INPUT ;
    USE SIGNAL ;
    PORT
      LAYER li1 ;
        RECT 0.095000 0.675000 0.335000 1.325000 ;
    END
  END B1
  PIN Y
    ANTENNADIFFAREA  0.447000 ;
    DIRECTION OUTPUT ;
    USE SIGNAL ;
    PORT
      LAYER li1 ;
        RECT 0.095000 1.495000 0.680000 1.685000 ;
        RECT 0.095000 1.685000 0.370000 2.455000 ;
        RECT 0.505000 0.645000 0.835000 0.825000 ;
        RECT 0.505000 0.825000 0.680000 1.495000 ;
        RECT 0.610000 0.265000 0.835000 0.645000 ;
    END
  END Y
  PIN VGND
    DIRECTION INOUT ;
    SHAPE ABUTMENT ;
    USE GROUND ;
    PORT
      LAYER met1 ;
        RECT 0.000000 -0.240000 1.840000 0.240000 ;
    END
  END VGND
  PIN VNB
    DIRECTION INOUT ;
    USE GROUND ;
    PORT
      LAYER pwell ;
        RECT 0.145000 -0.085000 0.315000 0.085000 ;
    END
  END VNB
  PIN VPB
    DIRECTION INOUT ;
    USE POWER ;
    PORT
      LAYER nwell ;
        RECT -0.190000 1.305000 2.030000 2.910000 ;
    END
  END VPB
  PIN VPWR
    DIRECTION INOUT ;
    SHAPE ABUTMENT ;
    USE POWER ;
    PORT
      LAYER met1 ;
        RECT 0.000000 2.480000 1.840000 2.960000 ;
    END
  END VPWR
  OBS
    LAYER li1 ;
      RECT 0.000000 -0.085000 1.840000 0.085000 ;
      RECT 0.000000  2.635000 1.840000 2.805000 ;
      RECT 0.110000  0.085000 0.440000 0.475000 ;
      RECT 0.540000  1.855000 1.745000 2.025000 ;
      RECT 0.540000  2.025000 0.870000 2.455000 ;
      RECT 0.850000  1.525000 1.745000 1.855000 ;
      RECT 1.040000  2.195000 1.235000 2.635000 ;
      RECT 1.415000  2.025000 1.745000 2.455000 ;
      RECT 1.445000  0.085000 1.745000 0.815000 ;
    LAYER mcon ;
      RECT 0.145000 -0.085000 0.315000 0.085000 ;
      RECT 0.145000  2.635000 0.315000 2.805000 ;
      RECT 0.605000 -0.085000 0.775000 0.085000 ;
      RECT 0.605000  2.635000 0.775000 2.805000 ;
      RECT 1.065000 -0.085000 1.235000 0.085000 ;
      RECT 1.065000  2.635000 1.235000 2.805000 ;
      RECT 1.525000 -0.085000 1.695000 0.085000 ;
      RECT 1.525000  2.635000 1.695000 2.805000 ;
  END
END sky130_fd_sc_hd__a21oi_1

MACRO sky130_fd_sc_hd__o21ai_1
  CLASS CORE ;
  FOREIGN sky130_fd_sc_hd__o21ai_1 ;
  ORIGIN  0.000000  0.000000 ;
  SIZE  1.840000 BY  2.720000 ;
  SYMMETRY X Y R90 ;
  SITE unithd ;
  PIN A1
    ANTENNAGATEAREA  0.247500 ;
    DIRECTION INPUT ;
    USE SIGNAL ;
    PORT
      LAYER li1 ;
        RECT 0.150000 0.995000 0.410000 1.325000 ;
    END
  END A1
  PIN A2
    ANTENNAGATEAREA  0.247500 ;
    DIRECTION INPUT ;
    USE SIGNAL ;
    PORT
      LAYER li1 ;
        RECT 0.590000 0.995000 0.975000 1.325000 ;
        RECT 0.590000 1.325000 0.785000 2.375000 ;
    END
  END A2
  PIN B1
    ANTENNAGATEAREA  0.202500 ;
    DIRECTION INPUT ;
    USE SIGNAL ;
    PORT
      LAYER li1 ;
        RECT 1.505000 1.295000 1.750000 1.655000 ;
    END
  END B1
  PIN Y
    ANTENNADIFFAREA  0.517000 ;
    DIRECTION OUTPUT ;
    USE SIGNAL ;
    PORT
      LAYER li1 ;
        RECT 0.965000 1.505000 1.315000 1.785000 ;
        RECT 0.965000 1.785000 1.295000 2.465000 ;
        RECT 1.145000 0.955000 1.665000 1.125000 ;
        RECT 1.145000 1.125000 1.315000 1.505000 ;
        RECT 1.495000 0.390000 1.665000 0.955000 ;
    END
  END Y
  PIN VGND
    DIRECTION INOUT ;
    SHAPE ABUTMENT ;
    USE GROUND ;
    PORT
      LAYER met1 ;
        RECT 0.000000 -0.240000 1.840000 0.240000 ;
    END
  END VGND
  PIN VNB
    DIRECTION INOUT ;
    USE GROUND ;
    PORT
      LAYER pwell ;
        RECT 0.150000 -0.085000 0.320000 0.085000 ;
    END
  END VNB
  PIN VPB
    DIRECTION INOUT ;
    USE POWER ;
    PORT
      LAYER nwell ;
        RECT -0.190000 1.305000 2.030000 2.910000 ;
    END
  END VPB
  PIN VPWR
    DIRECTION INOUT ;
    SHAPE ABUTMENT ;
    USE POWER ;
    PORT
      LAYER met1 ;
        RECT 0.000000 2.480000 1.840000 2.960000 ;
    END
  END VPWR
  OBS
    LAYER li1 ;
      RECT 0.000000 -0.085000 1.840000 0.085000 ;
      RECT 0.000000  2.635000 1.840000 2.805000 ;
      RECT 0.090000  0.265000 0.380000 0.615000 ;
      RECT 0.090000  0.615000 1.305000 0.785000 ;
      RECT 0.090000  1.495000 0.410000 2.635000 ;
      RECT 0.575000  0.085000 0.905000 0.445000 ;
      RECT 1.075000  0.310000 1.305000 0.615000 ;
      RECT 1.495000  1.835000 1.750000 2.635000 ;
    LAYER mcon ;
      RECT 0.145000 -0.085000 0.315000 0.085000 ;
      RECT 0.145000  2.635000 0.315000 2.805000 ;
      RECT 0.605000 -0.085000 0.775000 0.085000 ;
      RECT 0.605000  2.635000 0.775000 2.805000 ;
      RECT 1.065000 -0.085000 1.235000 0.085000 ;
      RECT 1.065000  2.635000 1.235000 2.805000 ;
      RECT 1.525000 -0.085000 1.695000 0.085000 ;
      RECT 1.525000  2.635000 1.695000 2.805000 ;
  END
END sky130_fd_sc_hd__o21ai_1

MACRO sky130_fd_sc_hd__mux2_1
  CLASS CORE ;
  FOREIGN sky130_fd_sc_hd__mux2_1 ;
  ORIGIN  0.000000  0.000000 ;
  SIZE  4.140000 BY  2.720000 ;
  SYMMETRY X Y R90 ;
  SITE unithd ;
  PIN A0
    ANTENNAGATEAREA  0.126000 ;
    DIRECTION INPUT ;
    USE SIGNAL ;
    PORT
      LAYER li1 ;
        RECT 1.990000 0.255000 2.265000 1.415000 ;
    END
  END A0
  PIN A1
    ANTENNAGATEAREA  0.126000 ;
    DIRECTION INPUT ;
    USE SIGNAL ;
    PORT
      LAYER li1 ;
        RECT 1.615000 0.815000 1.785000 1.615000 ;
        RECT 1.615000 1.615000 2.625000 1.785000 ;
        RECT 2.435000 0.255000 2.625000 1.615000 ;
    END
  END A1
  PIN S
    ANTENNAGATEAREA  0.252000 ;
    DIRECTION INPUT ;
    USE SIGNAL ;
    PORT
      LAYER li1 ;
        RECT 0.910000 0.995000 1.105000 1.325000 ;
        RECT 0.935000 1.325000 1.105000 2.295000 ;
        RECT 0.935000 2.295000 2.965000 2.465000 ;
        RECT 2.795000 1.440000 3.545000 1.630000 ;
        RECT 2.795000 1.630000 2.965000 2.295000 ;
    END
  END S
  PIN X
    ANTENNADIFFAREA  0.429000 ;
    DIRECTION OUTPUT ;
    USE SIGNAL ;
    PORT
      LAYER li1 ;
        RECT 0.090000 0.255000 0.345000 0.825000 ;
        RECT 0.090000 0.825000 0.260000 1.495000 ;
        RECT 0.090000 1.495000 0.425000 2.465000 ;
    END
  END X
  PIN VGND
    DIRECTION INOUT ;
    SHAPE ABUTMENT ;
    USE GROUND ;
    PORT
      LAYER met1 ;
        RECT 0.000000 -0.240000 4.140000 0.240000 ;
    END
  END VGND
  PIN VNB
    DIRECTION INOUT ;
    USE GROUND ;
    PORT
      LAYER pwell ;
        RECT 0.420000 -0.085000 0.590000 0.085000 ;
    END
  END VNB
  PIN VPB
    DIRECTION INOUT ;
    USE POWER ;
    PORT
      LAYER nwell ;
        RECT -0.190000 1.305000 4.330000 2.910000 ;
    END
  END VPB
  PIN VPWR
    DIRECTION INOUT ;
    SHAPE ABUTMENT ;
    USE POWER ;
    PORT
      LAYER met1 ;
        RECT 0.000000 2.480000 4.140000 2.960000 ;
    END
  END VPWR
  OBS
    LAYER li1 ;
      RECT 0.000000 -0.085000 4.140000 0.085000 ;
      RECT 0.000000  2.635000 4.140000 2.805000 ;
      RECT 0.430000  0.995000 0.685000 1.325000 ;
      RECT 0.515000  0.085000 0.845000 0.485000 ;
      RECT 0.515000  0.655000 1.445000 0.825000 ;
      RECT 0.515000  0.825000 0.685000 0.995000 ;
      RECT 0.595000  1.495000 0.765000 2.635000 ;
      RECT 1.270000  0.255000 1.800000 0.620000 ;
      RECT 1.270000  0.620000 1.445000 0.655000 ;
      RECT 1.275000  0.825000 1.445000 1.955000 ;
      RECT 1.275000  1.955000 2.400000 2.125000 ;
      RECT 2.805000  0.085000 3.315000 0.620000 ;
      RECT 2.825000  0.895000 4.055000 1.065000 ;
      RECT 3.135000  1.875000 3.305000 2.635000 ;
      RECT 3.535000  0.290000 3.780000 0.895000 ;
      RECT 3.540000  1.875000 4.055000 2.285000 ;
      RECT 3.715000  1.065000 4.055000 1.875000 ;
    LAYER mcon ;
      RECT 0.145000 -0.085000 0.315000 0.085000 ;
      RECT 0.145000  2.635000 0.315000 2.805000 ;
      RECT 0.605000 -0.085000 0.775000 0.085000 ;
      RECT 0.605000  2.635000 0.775000 2.805000 ;
      RECT 1.065000 -0.085000 1.235000 0.085000 ;
      RECT 1.065000  2.635000 1.235000 2.805000 ;
      RECT 1.525000 -0.085000 1.695000 0.085000 ;
      RECT 1.525000  2.635000 1.695000 2.805000 ;
      RECT 1.985000 -0.085000 2.155000 0.085000 ;
      RECT 1.985000  2.635000 2.155000 2.805000 ;
      RECT 2.445000 -0.085000 2.615000 0.085000 ;
      RECT 2.445000  2.635000 2.615000 2.805000 ;
      RECT 2.905000 -0.085000 3.075000 0.085000 ;
      RECT 2.905000  2.635000 3.075000 2.805000 ;
      RECT 3.365000 -0.085000 3.535000 0.085000 ;
      RECT 3.365000  2.635000 3.535000 2.805000 ;
      RECT 3.825000 -0.085000 3.995000 0.085000 ;
      RECT 3.825000  2.635000 3.995000 2.805000 ;
  END
END sky130_fd_sc_hd__mux2_1

MACRO sky130_fd_sc_hd__conb_1
  CLASS CORE ;
  FOREIGN sky130_fd_sc_hd__conb_1 ;
  ORIGIN  0.000000  0.000000 ;
  SIZE  1.380000 BY  2.720000 ;
  SYMMETRY X Y R90 ;
  SITE unithd ;
  PIN HI
    DIRECTION OUTPUT ;
    USE SIGNAL ;
    PORT
      LAYER li1 ;
        RECT 0.085000 0.255000 0.605000 1.740000 ;
    END
  END HI
  PIN LO
    DIRECTION OUTPUT ;
    USE SIGNAL ;
    PORT
      LAYER li1 ;
        RECT 0.775000 0.915000 1.295000 2.465000 ;
    END
  END LO
  PIN VGND
    DIRECTION INOUT ;
    SHAPE ABUTMENT ;
    USE GROUND ;
    PORT
      LAYER met1 ;
        RECT 0.000000 -0.240000 1.380000 0.240000 ;
    END
  END VGND
  PIN VNB
    DIRECTION INOUT ;
    USE GROUND ;
    PORT
      LAYER pwell ;
        RECT 0.145000 -0.085000 0.315000 0.085000 ;
    END
  END VNB
  PIN VPB
    DIRECTION INOUT ;
    USE POWER ;
    PORT
      LAYER nwell ;
        RECT -0.190000 1.305000 1.570000 2.910000 ;
    END
  END VPB
  PIN VPWR
    DIRECTION INOUT ;
    SHAPE ABUTMENT ;
    USE POWER ;
    PORT
      LAYER met1 ;
        RECT 0.000000 2.480000 1.380000 2.960000 ;
    END
  END VPWR
  OBS
    LAYER li1 ;
      RECT 0.000000 -0.085000 1.380000 0.085000 ;
      RECT 0.000000  2.635000 1.380000 2.805000 ;
      RECT 0.275000  1.910000 0.605000 2.635000 ;
      RECT 0.775000  0.085000 1.115000 0.745000 ;
    LAYER mcon ;
      RECT 0.145000 -0.085000 0.315000 0.085000 ;
      RECT 0.145000  2.635000 0.315000 2.805000 ;
      RECT 0.605000 -0.085000 0.775000 0.085000 ;
      RECT 0.605000  2.635000 0.775000 2.805000 ;
      RECT 1.065000 -0.085000 1.235000 0.085000 ;
      RECT 1.065000  2.635000 1.235000 2.805000 ;
  END
END sky130_fd_sc_hd__conb_1

MACRO sky130_fd_sc_hd__dfxtp_1
  CLASS CORE ;
  FOREIGN sky130_fd_sc_hd__dfxtp_1 ;
  ORIGIN  0.000000  0.000000 ;
  SIZE  7.360000 BY  2.720000 ;
  SYMMETRY X Y R90 ;
  SITE unithd ;
  PIN D
    ANTENNAGATEAREA  0.126000 ;
    DIRECTION INPUT ;
    USE SIGNAL ;
    PORT
      LAYER li1 ;
        RECT 1.370000 0.715000 1.650000 1.665000 ;
    END
  END D
  PIN Q
    ANTENNADIFFAREA  0.429000 ;
    DIRECTION OUTPUT ;
    USE SIGNAL ;
    PORT
      LAYER li1 ;
        RECT 6.885000 1.495000 7.275000 1.575000 ;
        RECT 6.885000 1.575000 7.215000 2.420000 ;
        RECT 6.895000 0.305000 7.225000 0.740000 ;
        RECT 6.895000 0.740000 7.275000 0.825000 ;
        RECT 7.050000 0.825000 7.275000 0.865000 ;
        RECT 7.060000 1.445000 7.275000 1.495000 ;
        RECT 7.105000 0.865000 7.275000 1.445000 ;
    END
  END Q
  PIN CLK
    ANTENNAGATEAREA  0.159000 ;
    DIRECTION INPUT ;
    USE CLOCK ;
    PORT
      LAYER li1 ;
        RECT 0.090000 0.975000 0.440000 1.625000 ;
    END
  END CLK
  PIN VGND
    DIRECTION INOUT ;
    SHAPE ABUTMENT ;
    USE GROUND ;
    PORT
      LAYER met1 ;
        RECT 0.000000 -0.240000 7.360000 0.240000 ;
    END
  END VGND
  PIN VNB
    DIRECTION INOUT ;
    USE GROUND ;
    PORT
      LAYER pwell ;
        RECT 0.145000 -0.085000 0.315000 0.085000 ;
    END
  END VNB
  PIN VPB
    DIRECTION INOUT ;
    USE POWER ;
    PORT
      LAYER nwell ;
        RECT -0.190000 1.305000 7.550000 2.910000 ;
    END
  END VPB
  PIN VPWR
    DIRECTION INOUT ;
    SHAPE ABUTMENT ;
    USE POWER ;
    PORT
      LAYER met1 ;
        RECT 0.000000 2.480000 7.360000 2.960000 ;
    END
  END VPWR
  OBS
    LAYER li1 ;
      RECT 0.000000 -0.085000 7.360000 0.085000 ;
      RECT 0.000000  2.635000 7.360000 2.805000 ;
      RECT 0.175000  0.345000 0.345000 0.635000 ;
      RECT 0.175000  0.635000 0.840000 0.805000 ;
      RECT 0.175000  1.795000 0.840000 1.965000 ;
      RECT 0.175000  1.965000 0.345000 2.465000 ;
      RECT 0.515000  0.085000 0.845000 0.465000 ;
      RECT 0.515000  2.135000 0.845000 2.635000 ;
      RECT 0.610000  0.805000 0.840000 1.795000 ;
      RECT 1.015000  0.345000 1.200000 2.465000 ;
      RECT 1.440000  2.175000 1.705000 2.635000 ;
      RECT 1.455000  0.085000 1.705000 0.545000 ;
      RECT 1.820000  0.675000 2.045000 0.805000 ;
      RECT 1.820000  0.805000 1.990000 1.910000 ;
      RECT 1.820000  1.910000 2.125000 2.040000 ;
      RECT 1.875000  0.365000 2.210000 0.535000 ;
      RECT 1.875000  0.535000 2.045000 0.675000 ;
      RECT 1.875000  2.040000 2.125000 2.465000 ;
      RECT 2.160000  1.125000 2.400000 1.720000 ;
      RECT 2.215000  0.735000 2.740000 0.955000 ;
      RECT 2.335000  2.190000 3.440000 2.360000 ;
      RECT 2.405000  0.365000 3.080000 0.535000 ;
      RECT 2.570000  0.955000 2.740000 1.655000 ;
      RECT 2.570000  1.655000 3.100000 2.020000 ;
      RECT 2.910000  0.535000 3.080000 1.315000 ;
      RECT 2.910000  1.315000 3.780000 1.485000 ;
      RECT 3.270000  1.485000 3.780000 1.575000 ;
      RECT 3.270000  1.575000 3.440000 2.190000 ;
      RECT 3.290000  0.765000 4.120000 1.065000 ;
      RECT 3.290000  1.065000 3.490000 1.095000 ;
      RECT 3.400000  0.085000 3.770000 0.585000 ;
      RECT 3.610000  1.245000 3.780000 1.315000 ;
      RECT 3.610000  1.835000 3.780000 2.635000 ;
      RECT 3.950000  0.365000 4.355000 0.535000 ;
      RECT 3.950000  0.535000 4.120000 0.765000 ;
      RECT 3.950000  1.065000 4.120000 2.135000 ;
      RECT 3.950000  2.135000 4.200000 2.465000 ;
      RECT 4.290000  1.245000 4.480000 1.965000 ;
      RECT 4.425000  2.165000 5.310000 2.335000 ;
      RECT 4.505000  0.705000 4.970000 1.035000 ;
      RECT 4.525000  0.365000 5.310000 0.535000 ;
      RECT 4.650000  1.035000 4.970000 1.995000 ;
      RECT 5.140000  0.535000 5.310000 0.995000 ;
      RECT 5.140000  0.995000 6.015000 1.325000 ;
      RECT 5.140000  1.325000 5.310000 2.165000 ;
      RECT 5.480000  1.530000 6.375000 1.905000 ;
      RECT 5.490000  2.135000 5.805000 2.635000 ;
      RECT 5.585000  0.085000 5.795000 0.615000 ;
      RECT 6.035000  1.905000 6.375000 2.465000 ;
      RECT 6.055000  0.300000 6.385000 0.825000 ;
      RECT 6.185000  0.825000 6.385000 0.995000 ;
      RECT 6.185000  0.995000 6.935000 1.325000 ;
      RECT 6.185000  1.325000 6.375000 1.530000 ;
      RECT 6.545000  1.625000 6.715000 2.635000 ;
      RECT 6.555000  0.085000 6.725000 0.695000 ;
    LAYER mcon ;
      RECT 0.145000 -0.085000 0.315000 0.085000 ;
      RECT 0.145000  2.635000 0.315000 2.805000 ;
      RECT 0.605000 -0.085000 0.775000 0.085000 ;
      RECT 0.605000  2.635000 0.775000 2.805000 ;
      RECT 0.630000  1.785000 0.800000 1.955000 ;
      RECT 1.025000  1.445000 1.195000 1.615000 ;
      RECT 1.065000 -0.085000 1.235000 0.085000 ;
      RECT 1.065000  2.635000 1.235000 2.805000 ;
      RECT 1.525000 -0.085000 1.695000 0.085000 ;
      RECT 1.525000  2.635000 1.695000 2.805000 ;
      RECT 1.985000 -0.085000 2.155000 0.085000 ;
      RECT 1.985000  2.635000 2.155000 2.805000 ;
      RECT 2.215000  1.445000 2.385000 1.615000 ;
      RECT 2.445000 -0.085000 2.615000 0.085000 ;
      RECT 2.445000  2.635000 2.615000 2.805000 ;
      RECT 2.730000  1.785000 2.900000 1.955000 ;
      RECT 2.905000 -0.085000 3.075000 0.085000 ;
      RECT 2.905000  2.635000 3.075000 2.805000 ;
      RECT 3.365000 -0.085000 3.535000 0.085000 ;
      RECT 3.365000  2.635000 3.535000 2.805000 ;
      RECT 3.825000 -0.085000 3.995000 0.085000 ;
      RECT 3.825000  2.635000 3.995000 2.805000 ;
      RECT 4.285000 -0.085000 4.455000 0.085000 ;
      RECT 4.285000  2.635000 4.455000 2.805000 ;
      RECT 4.300000  1.785000 4.470000 1.955000 ;
      RECT 4.735000  1.445000 4.905000 1.615000 ;
      RECT 4.745000 -0.085000 4.915000 0.085000 ;
      RECT 4.745000  2.635000 4.915000 2.805000 ;
      RECT 5.205000 -0.085000 5.375000 0.085000 ;
      RECT 5.205000  2.635000 5.375000 2.805000 ;
      RECT 5.665000 -0.085000 5.835000 0.085000 ;
      RECT 5.665000  2.635000 5.835000 2.805000 ;
      RECT 6.125000 -0.085000 6.295000 0.085000 ;
      RECT 6.125000  2.635000 6.295000 2.805000 ;
      RECT 6.585000 -0.085000 6.755000 0.085000 ;
      RECT 6.585000  2.635000 6.755000 2.805000 ;
      RECT 7.045000 -0.085000 7.215000 0.085000 ;
      RECT 7.045000  2.635000 7.215000 2.805000 ;
    LAYER met1 ;
      RECT 0.570000 1.755000 0.860000 1.800000 ;
      RECT 0.570000 1.800000 4.530000 1.940000 ;
      RECT 0.570000 1.940000 0.860000 1.985000 ;
      RECT 0.965000 1.415000 1.255000 1.460000 ;
      RECT 0.965000 1.460000 4.965000 1.600000 ;
      RECT 0.965000 1.600000 1.255000 1.645000 ;
      RECT 2.155000 1.415000 2.445000 1.460000 ;
      RECT 2.155000 1.600000 2.445000 1.645000 ;
      RECT 2.670000 1.755000 2.960000 1.800000 ;
      RECT 2.670000 1.940000 2.960000 1.985000 ;
      RECT 4.240000 1.755000 4.530000 1.800000 ;
      RECT 4.240000 1.940000 4.530000 1.985000 ;
      RECT 4.675000 1.415000 4.965000 1.460000 ;
      RECT 4.675000 1.600000 4.965000 1.645000 ;
  END
END sky130_fd_sc_hd__dfxtp_1

MACRO sky130_fd_sc_hd__dfrtp_1
  CLASS CORE ;
  FOREIGN sky130_fd_sc_hd__dfrtp_1 ;
  ORIGIN  0.000000  0.000000 ;
  SIZE  9.200000 BY  2.720000 ;
  SYMMETRY X Y R90 ;
  SITE unithd ;
  PIN D
    ANTENNAGATEAREA  0.126000 ;
    DIRECTION INPUT ;
    USE SIGNAL ;
    PORT
      LAYER li1 ;
        RECT 1.355000 1.665000 1.680000 2.450000 ;
        RECT 1.415000 0.615000 1.875000 1.665000 ;
    END
  END D
  PIN Q
    ANTENNADIFFAREA  0.429000 ;
    DIRECTION OUTPUT ;
    USE SIGNAL ;
    PORT
      LAYER li1 ;
        RECT 8.855000 0.265000 9.110000 0.795000 ;
        RECT 8.855000 1.445000 9.110000 2.325000 ;
        RECT 8.900000 0.795000 9.110000 1.445000 ;
    END
  END Q
  PIN RESET_B
    ANTENNAGATEAREA  0.252000 ;
    DIRECTION INPUT ;
    USE SIGNAL ;
    PORT
      LAYER li1 ;
        RECT 3.805000 0.765000 4.595000 1.015000 ;
      LAYER mcon ;
        RECT 4.165000 0.765000 4.335000 0.935000 ;
    END
    PORT
      LAYER li1 ;
        RECT 7.105000 1.035000 7.645000 1.405000 ;
        RECT 7.405000 0.635000 7.645000 1.035000 ;
      LAYER mcon ;
        RECT 7.105000 1.080000 7.275000 1.250000 ;
        RECT 7.405000 0.765000 7.575000 0.935000 ;
    END
    PORT
      LAYER met1 ;
        RECT 3.745000 0.735000 4.395000 0.780000 ;
        RECT 3.745000 0.780000 7.635000 0.920000 ;
        RECT 3.745000 0.920000 4.395000 0.965000 ;
        RECT 7.045000 0.920000 7.635000 0.965000 ;
        RECT 7.045000 0.965000 7.335000 1.280000 ;
        RECT 7.345000 0.735000 7.635000 0.780000 ;
    END
  END RESET_B
  PIN CLK
    ANTENNAGATEAREA  0.159000 ;
    DIRECTION INPUT ;
    USE CLOCK ;
    PORT
      LAYER li1 ;
        RECT 0.090000 0.975000 0.440000 1.625000 ;
    END
  END CLK
  PIN VGND
    DIRECTION INOUT ;
    SHAPE ABUTMENT ;
    USE GROUND ;
    PORT
      LAYER met1 ;
        RECT 0.000000 -0.240000 9.200000 0.240000 ;
    END
  END VGND
  PIN VNB
    DIRECTION INOUT ;
    USE GROUND ;
    PORT
      LAYER pwell ;
        RECT 0.145000 -0.085000 0.315000 0.085000 ;
    END
  END VNB
  PIN VPB
    DIRECTION INOUT ;
    USE POWER ;
    PORT
      LAYER nwell ;
        RECT -0.190000 1.305000 9.390000 2.910000 ;
    END
  END VPB
  PIN VPWR
    DIRECTION INOUT ;
    SHAPE ABUTMENT ;
    USE POWER ;
    PORT
      LAYER met1 ;
        RECT 0.000000 2.480000 9.200000 2.960000 ;
    END
  END VPWR
  OBS
    LAYER li1 ;
      RECT 0.000000 -0.085000 9.200000 0.085000 ;
      RECT 0.000000  2.635000 9.200000 2.805000 ;
      RECT 0.090000  0.345000 0.345000 0.635000 ;
      RECT 0.090000  0.635000 0.840000 0.805000 ;
      RECT 0.090000  1.795000 0.840000 1.965000 ;
      RECT 0.090000  1.965000 0.345000 2.465000 ;
      RECT 0.515000  0.085000 0.845000 0.465000 ;
      RECT 0.515000  2.135000 0.845000 2.635000 ;
      RECT 0.610000  0.805000 0.840000 1.795000 ;
      RECT 1.015000  0.345000 1.185000 2.465000 ;
      RECT 1.545000  0.085000 1.875000 0.445000 ;
      RECT 1.850000  2.175000 2.100000 2.635000 ;
      RECT 2.045000  0.305000 2.540000 0.475000 ;
      RECT 2.045000  0.475000 2.215000 1.835000 ;
      RECT 2.045000  1.835000 2.440000 2.005000 ;
      RECT 2.270000  2.005000 2.440000 2.135000 ;
      RECT 2.270000  2.135000 2.520000 2.465000 ;
      RECT 2.385000  0.765000 2.735000 1.385000 ;
      RECT 2.610000  1.575000 3.075000 1.965000 ;
      RECT 2.735000  2.135000 3.415000 2.465000 ;
      RECT 2.745000  0.305000 3.600000 0.475000 ;
      RECT 2.905000  0.765000 3.260000 0.985000 ;
      RECT 2.905000  0.985000 3.075000 1.575000 ;
      RECT 3.245000  1.185000 4.935000 1.355000 ;
      RECT 3.245000  1.355000 3.415000 2.135000 ;
      RECT 3.430000  0.475000 3.600000 1.185000 ;
      RECT 3.585000  1.865000 4.660000 2.035000 ;
      RECT 3.585000  2.035000 3.755000 2.375000 ;
      RECT 3.775000  1.525000 5.275000 1.695000 ;
      RECT 3.990000  2.205000 4.320000 2.635000 ;
      RECT 4.475000  0.085000 4.805000 0.545000 ;
      RECT 4.490000  2.035000 4.660000 2.375000 ;
      RECT 4.765000  1.005000 4.935000 1.185000 ;
      RECT 4.955000  2.175000 5.325000 2.635000 ;
      RECT 5.015000  0.275000 5.365000 0.445000 ;
      RECT 5.015000  0.445000 5.275000 0.835000 ;
      RECT 5.105000  0.835000 5.275000 1.525000 ;
      RECT 5.105000  1.695000 5.275000 1.835000 ;
      RECT 5.105000  1.835000 5.665000 2.005000 ;
      RECT 5.465000  0.705000 5.675000 1.495000 ;
      RECT 5.465000  1.495000 6.140000 1.655000 ;
      RECT 5.465000  1.655000 6.430000 1.665000 ;
      RECT 5.495000  2.005000 5.665000 2.465000 ;
      RECT 5.585000  0.255000 6.535000 0.535000 ;
      RECT 5.845000  0.705000 6.195000 1.325000 ;
      RECT 5.900000  2.125000 6.770000 2.465000 ;
      RECT 5.970000  1.665000 6.430000 1.955000 ;
      RECT 6.365000  0.535000 6.535000 1.315000 ;
      RECT 6.365000  1.315000 6.770000 1.485000 ;
      RECT 6.600000  1.485000 6.770000 1.575000 ;
      RECT 6.600000  1.575000 7.820000 1.745000 ;
      RECT 6.600000  1.745000 6.770000 2.125000 ;
      RECT 6.705000  0.085000 6.895000 0.525000 ;
      RECT 6.705000  0.695000 7.235000 0.865000 ;
      RECT 6.705000  0.865000 6.925000 1.145000 ;
      RECT 6.940000  2.175000 7.190000 2.635000 ;
      RECT 7.065000  0.295000 8.135000 0.465000 ;
      RECT 7.065000  0.465000 7.235000 0.695000 ;
      RECT 7.360000  1.915000 8.160000 2.085000 ;
      RECT 7.360000  2.085000 7.530000 2.375000 ;
      RECT 7.710000  2.255000 8.040000 2.635000 ;
      RECT 7.815000  0.465000 8.135000 0.820000 ;
      RECT 7.815000  0.820000 8.140000 0.995000 ;
      RECT 7.815000  0.995000 8.730000 1.295000 ;
      RECT 7.990000  1.295000 8.730000 1.325000 ;
      RECT 7.990000  1.325000 8.160000 1.915000 ;
      RECT 8.380000  0.085000 8.685000 0.545000 ;
      RECT 8.380000  1.495000 8.685000 2.635000 ;
    LAYER mcon ;
      RECT 0.145000 -0.085000 0.315000 0.085000 ;
      RECT 0.145000  2.635000 0.315000 2.805000 ;
      RECT 0.605000 -0.085000 0.775000 0.085000 ;
      RECT 0.605000  2.635000 0.775000 2.805000 ;
      RECT 0.610000  1.105000 0.780000 1.275000 ;
      RECT 1.015000  1.785000 1.185000 1.955000 ;
      RECT 1.065000 -0.085000 1.235000 0.085000 ;
      RECT 1.065000  2.635000 1.235000 2.805000 ;
      RECT 1.525000 -0.085000 1.695000 0.085000 ;
      RECT 1.525000  2.635000 1.695000 2.805000 ;
      RECT 1.985000 -0.085000 2.155000 0.085000 ;
      RECT 1.985000  2.635000 2.155000 2.805000 ;
      RECT 2.445000 -0.085000 2.615000 0.085000 ;
      RECT 2.445000  1.105000 2.615000 1.275000 ;
      RECT 2.445000  2.635000 2.615000 2.805000 ;
      RECT 2.905000 -0.085000 3.075000 0.085000 ;
      RECT 2.905000  1.785000 3.075000 1.955000 ;
      RECT 2.905000  2.635000 3.075000 2.805000 ;
      RECT 3.365000 -0.085000 3.535000 0.085000 ;
      RECT 3.365000  2.635000 3.535000 2.805000 ;
      RECT 3.825000 -0.085000 3.995000 0.085000 ;
      RECT 3.825000  2.635000 3.995000 2.805000 ;
      RECT 4.285000 -0.085000 4.455000 0.085000 ;
      RECT 4.285000  2.635000 4.455000 2.805000 ;
      RECT 4.745000 -0.085000 4.915000 0.085000 ;
      RECT 4.745000  2.635000 4.915000 2.805000 ;
      RECT 5.205000 -0.085000 5.375000 0.085000 ;
      RECT 5.205000  2.635000 5.375000 2.805000 ;
      RECT 5.665000 -0.085000 5.835000 0.085000 ;
      RECT 5.665000  2.635000 5.835000 2.805000 ;
      RECT 6.025000  1.105000 6.195000 1.275000 ;
      RECT 6.025000  1.785000 6.195000 1.955000 ;
      RECT 6.125000 -0.085000 6.295000 0.085000 ;
      RECT 6.125000  2.635000 6.295000 2.805000 ;
      RECT 6.585000 -0.085000 6.755000 0.085000 ;
      RECT 6.585000  2.635000 6.755000 2.805000 ;
      RECT 7.045000 -0.085000 7.215000 0.085000 ;
      RECT 7.045000  2.635000 7.215000 2.805000 ;
      RECT 7.505000 -0.085000 7.675000 0.085000 ;
      RECT 7.505000  2.635000 7.675000 2.805000 ;
      RECT 7.965000 -0.085000 8.135000 0.085000 ;
      RECT 7.965000  2.635000 8.135000 2.805000 ;
      RECT 8.425000 -0.085000 8.595000 0.085000 ;
      RECT 8.425000  2.635000 8.595000 2.805000 ;
      RECT 8.885000 -0.085000 9.055000 0.085000 ;
      RECT 8.885000  2.635000 9.055000 2.805000 ;
    LAYER met1 ;
      RECT 0.550000 1.075000 0.840000 1.120000 ;
      RECT 0.550000 1.120000 6.255000 1.260000 ;
      RECT 0.550000 1.260000 0.840000 1.305000 ;
      RECT 0.955000 1.755000 1.245000 1.800000 ;
      RECT 0.955000 1.800000 6.255000 1.940000 ;
      RECT 0.955000 1.940000 1.245000 1.985000 ;
      RECT 2.385000 1.075000 2.675000 1.120000 ;
      RECT 2.385000 1.260000 2.675000 1.305000 ;
      RECT 2.845000 1.755000 3.135000 1.800000 ;
      RECT 2.845000 1.940000 3.135000 1.985000 ;
      RECT 5.965000 1.075000 6.255000 1.120000 ;
      RECT 5.965000 1.260000 6.255000 1.305000 ;
      RECT 5.965000 1.755000 6.255000 1.800000 ;
      RECT 5.965000 1.940000 6.255000 1.985000 ;
  END
END sky130_fd_sc_hd__dfrtp_1

MACRO sky130_fd_sc_hd__dfstp_1
  CLASS CORE ;
  FOREIGN sky130_fd_sc_hd__dfstp_1 ;
  ORIGIN  0.000000  0.000000 ;
  SIZE  9.660000 BY  2.720000 ;
  SYMMETRY X Y R90 ;
  SITE unithd ;
  PIN D
    ANTENNAGATEAREA  0.222000 ;
    DIRECTION INPUT ;
    USE SIGNAL ;
    PORT
      LAYER li1 ;
        RECT 1.770000 1.005000 2.180000 1.625000 ;
    END
  END D
  PIN Q
    ANTENNADIFFAREA  0.429000 ;
    DIRECTION OUTPUT ;
    USE SIGNAL ;
    PORT
      LAYER li1 ;
        RECT 8.945000 0.265000 9.200000 0.795000 ;
        RECT 8.945000 1.655000 9.200000 2.325000 ;
        RECT 9.020000 0.795000 9.200000 1.655000 ;
    END
  END Q
  PIN SET_B
    ANTENNAGATEAREA  0.252000 ;
    DIRECTION INPUT ;
    USE SIGNAL ;
    PORT
      LAYER li1 ;
        RECT 3.610000 0.735000 4.020000 1.065000 ;
      LAYER mcon ;
        RECT 3.850000 0.765000 4.020000 0.935000 ;
    END
    PORT
      LAYER li1 ;
        RECT 6.680000 0.735000 7.340000 1.005000 ;
        RECT 6.680000 1.005000 7.010000 1.065000 ;
      LAYER mcon ;
        RECT 7.110000 0.765000 7.280000 0.935000 ;
    END
    PORT
      LAYER met1 ;
        RECT 3.790000 0.735000 4.080000 0.780000 ;
        RECT 3.790000 0.780000 7.340000 0.920000 ;
        RECT 3.790000 0.920000 4.080000 0.965000 ;
        RECT 7.050000 0.735000 7.340000 0.780000 ;
        RECT 7.050000 0.920000 7.340000 0.965000 ;
    END
  END SET_B
  PIN CLK
    ANTENNAGATEAREA  0.159000 ;
    DIRECTION INPUT ;
    USE CLOCK ;
    PORT
      LAYER li1 ;
        RECT 0.090000 0.975000 0.440000 1.625000 ;
    END
  END CLK
  PIN VGND
    DIRECTION INOUT ;
    SHAPE ABUTMENT ;
    USE GROUND ;
    PORT
      LAYER met1 ;
        RECT 0.000000 -0.240000 9.660000 0.240000 ;
    END
  END VGND
  PIN VNB
    DIRECTION INOUT ;
    USE GROUND ;
    PORT
      LAYER pwell ;
        RECT 0.145000 -0.085000 0.315000 0.085000 ;
    END
  END VNB
  PIN VPB
    DIRECTION INOUT ;
    USE POWER ;
    PORT
      LAYER nwell ;
        RECT -0.190000 1.305000 9.850000 2.910000 ;
    END
  END VPB
  PIN VPWR
    DIRECTION INOUT ;
    SHAPE ABUTMENT ;
    USE POWER ;
    PORT
      LAYER met1 ;
        RECT 0.000000 2.480000 9.660000 2.960000 ;
    END
  END VPWR
  OBS
    LAYER li1 ;
      RECT 0.000000 -0.085000 9.660000 0.085000 ;
      RECT 0.000000  2.635000 9.660000 2.805000 ;
      RECT 0.175000  0.345000 0.345000 0.635000 ;
      RECT 0.175000  0.635000 0.840000 0.805000 ;
      RECT 0.175000  1.795000 0.840000 1.965000 ;
      RECT 0.175000  1.965000 0.345000 2.465000 ;
      RECT 0.515000  0.085000 0.845000 0.465000 ;
      RECT 0.515000  2.135000 0.845000 2.635000 ;
      RECT 0.610000  0.805000 0.840000 1.795000 ;
      RECT 1.015000  0.345000 1.240000 2.465000 ;
      RECT 1.430000  0.635000 2.125000 0.825000 ;
      RECT 1.430000  0.825000 1.600000 1.795000 ;
      RECT 1.430000  1.795000 2.125000 1.965000 ;
      RECT 1.455000  0.085000 1.785000 0.465000 ;
      RECT 1.455000  2.135000 1.785000 2.635000 ;
      RECT 1.955000  0.305000 2.125000 0.635000 ;
      RECT 1.955000  1.965000 2.125000 2.465000 ;
      RECT 2.350000  0.705000 2.570000 1.575000 ;
      RECT 2.350000  1.575000 2.850000 1.955000 ;
      RECT 2.360000  2.250000 3.190000 2.420000 ;
      RECT 2.425000  0.265000 3.440000 0.465000 ;
      RECT 2.750000  0.645000 3.100000 1.015000 ;
      RECT 3.020000  1.195000 3.440000 1.235000 ;
      RECT 3.020000  1.235000 4.370000 1.405000 ;
      RECT 3.020000  1.405000 3.190000 2.250000 ;
      RECT 3.270000  0.465000 3.440000 1.195000 ;
      RECT 3.360000  1.575000 3.610000 1.835000 ;
      RECT 3.360000  1.835000 4.730000 2.085000 ;
      RECT 3.430000  2.255000 3.810000 2.635000 ;
      RECT 3.610000  0.085000 4.020000 0.525000 ;
      RECT 3.990000  2.085000 4.160000 2.375000 ;
      RECT 4.120000  1.405000 4.370000 1.565000 ;
      RECT 4.310000  0.295000 4.560000 0.725000 ;
      RECT 4.310000  0.725000 4.730000 1.065000 ;
      RECT 4.330000  2.255000 4.660000 2.635000 ;
      RECT 4.540000  1.065000 4.730000 1.835000 ;
      RECT 4.760000  0.085000 5.080000 0.545000 ;
      RECT 4.900000  0.725000 6.150000 0.895000 ;
      RECT 4.900000  0.895000 5.070000 1.655000 ;
      RECT 4.900000  1.655000 5.420000 1.965000 ;
      RECT 5.130000  2.165000 5.760000 2.415000 ;
      RECT 5.240000  1.065000 5.420000 1.475000 ;
      RECT 5.590000  1.235000 7.490000 1.405000 ;
      RECT 5.590000  1.405000 5.760000 1.915000 ;
      RECT 5.590000  1.915000 6.800000 2.085000 ;
      RECT 5.590000  2.085000 5.760000 2.165000 ;
      RECT 5.640000  0.305000 6.490000 0.475000 ;
      RECT 5.820000  0.895000 6.150000 1.015000 ;
      RECT 5.930000  1.575000 7.850000 1.745000 ;
      RECT 5.940000  2.255000 6.360000 2.635000 ;
      RECT 6.320000  0.475000 6.490000 1.235000 ;
      RECT 6.560000  2.085000 6.800000 2.375000 ;
      RECT 6.690000  0.085000 7.350000 0.565000 ;
      RECT 7.030000  1.945000 7.360000 2.635000 ;
      RECT 7.160000  1.175000 7.490000 1.235000 ;
      RECT 7.530000  0.350000 7.850000 0.680000 ;
      RECT 7.530000  1.745000 7.850000 1.765000 ;
      RECT 7.530000  1.765000 7.700000 2.375000 ;
      RECT 7.660000  0.680000 7.850000 1.575000 ;
      RECT 7.970000  1.915000 8.300000 2.425000 ;
      RECT 8.050000  0.345000 8.300000 0.995000 ;
      RECT 8.050000  0.995000 8.850000 1.325000 ;
      RECT 8.050000  1.325000 8.300000 1.915000 ;
      RECT 8.480000  0.085000 8.765000 0.545000 ;
      RECT 8.480000  1.835000 8.765000 2.635000 ;
    LAYER mcon ;
      RECT 0.145000 -0.085000 0.315000 0.085000 ;
      RECT 0.145000  2.635000 0.315000 2.805000 ;
      RECT 0.605000 -0.085000 0.775000 0.085000 ;
      RECT 0.605000  2.635000 0.775000 2.805000 ;
      RECT 0.610000  1.785000 0.780000 1.955000 ;
      RECT 1.065000 -0.085000 1.235000 0.085000 ;
      RECT 1.065000  2.635000 1.235000 2.805000 ;
      RECT 1.070000  0.765000 1.240000 0.935000 ;
      RECT 1.525000 -0.085000 1.695000 0.085000 ;
      RECT 1.525000  2.635000 1.695000 2.805000 ;
      RECT 1.985000 -0.085000 2.155000 0.085000 ;
      RECT 1.985000  2.635000 2.155000 2.805000 ;
      RECT 2.445000 -0.085000 2.615000 0.085000 ;
      RECT 2.445000  2.635000 2.615000 2.805000 ;
      RECT 2.470000  1.785000 2.640000 1.955000 ;
      RECT 2.905000 -0.085000 3.075000 0.085000 ;
      RECT 2.905000  2.635000 3.075000 2.805000 ;
      RECT 2.930000  0.765000 3.100000 0.935000 ;
      RECT 3.365000 -0.085000 3.535000 0.085000 ;
      RECT 3.365000  2.635000 3.535000 2.805000 ;
      RECT 3.825000 -0.085000 3.995000 0.085000 ;
      RECT 3.825000  2.635000 3.995000 2.805000 ;
      RECT 4.285000 -0.085000 4.455000 0.085000 ;
      RECT 4.285000  2.635000 4.455000 2.805000 ;
      RECT 4.745000 -0.085000 4.915000 0.085000 ;
      RECT 4.745000  2.635000 4.915000 2.805000 ;
      RECT 5.205000 -0.085000 5.375000 0.085000 ;
      RECT 5.205000  2.635000 5.375000 2.805000 ;
      RECT 5.250000  1.105000 5.420000 1.275000 ;
      RECT 5.250000  1.785000 5.420000 1.955000 ;
      RECT 5.665000 -0.085000 5.835000 0.085000 ;
      RECT 5.665000  2.635000 5.835000 2.805000 ;
      RECT 6.125000 -0.085000 6.295000 0.085000 ;
      RECT 6.125000  2.635000 6.295000 2.805000 ;
      RECT 6.585000 -0.085000 6.755000 0.085000 ;
      RECT 6.585000  2.635000 6.755000 2.805000 ;
      RECT 7.045000 -0.085000 7.215000 0.085000 ;
      RECT 7.045000  2.635000 7.215000 2.805000 ;
      RECT 7.505000 -0.085000 7.675000 0.085000 ;
      RECT 7.505000  2.635000 7.675000 2.805000 ;
      RECT 7.965000 -0.085000 8.135000 0.085000 ;
      RECT 7.965000  2.635000 8.135000 2.805000 ;
      RECT 8.425000 -0.085000 8.595000 0.085000 ;
      RECT 8.425000  2.635000 8.595000 2.805000 ;
      RECT 8.885000 -0.085000 9.055000 0.085000 ;
      RECT 8.885000  2.635000 9.055000 2.805000 ;
      RECT 9.345000 -0.085000 9.515000 0.085000 ;
      RECT 9.345000  2.635000 9.515000 2.805000 ;
    LAYER met1 ;
      RECT 0.550000 1.755000 0.840000 1.800000 ;
      RECT 0.550000 1.800000 5.480000 1.940000 ;
      RECT 0.550000 1.940000 0.840000 1.985000 ;
      RECT 1.010000 0.735000 1.300000 0.780000 ;
      RECT 1.010000 0.780000 3.160000 0.920000 ;
      RECT 1.010000 0.920000 1.300000 0.965000 ;
      RECT 2.410000 1.755000 2.700000 1.800000 ;
      RECT 2.410000 1.940000 2.700000 1.985000 ;
      RECT 2.870000 0.735000 3.160000 0.780000 ;
      RECT 2.870000 0.920000 3.160000 0.965000 ;
      RECT 2.945000 0.965000 3.160000 1.120000 ;
      RECT 2.945000 1.120000 5.480000 1.260000 ;
      RECT 5.190000 1.075000 5.480000 1.120000 ;
      RECT 5.190000 1.260000 5.480000 1.305000 ;
      RECT 5.190000 1.755000 5.480000 1.800000 ;
      RECT 5.190000 1.940000 5.480000 1.985000 ;
  END
END sky130_fd_sc_hd__dfstp_1

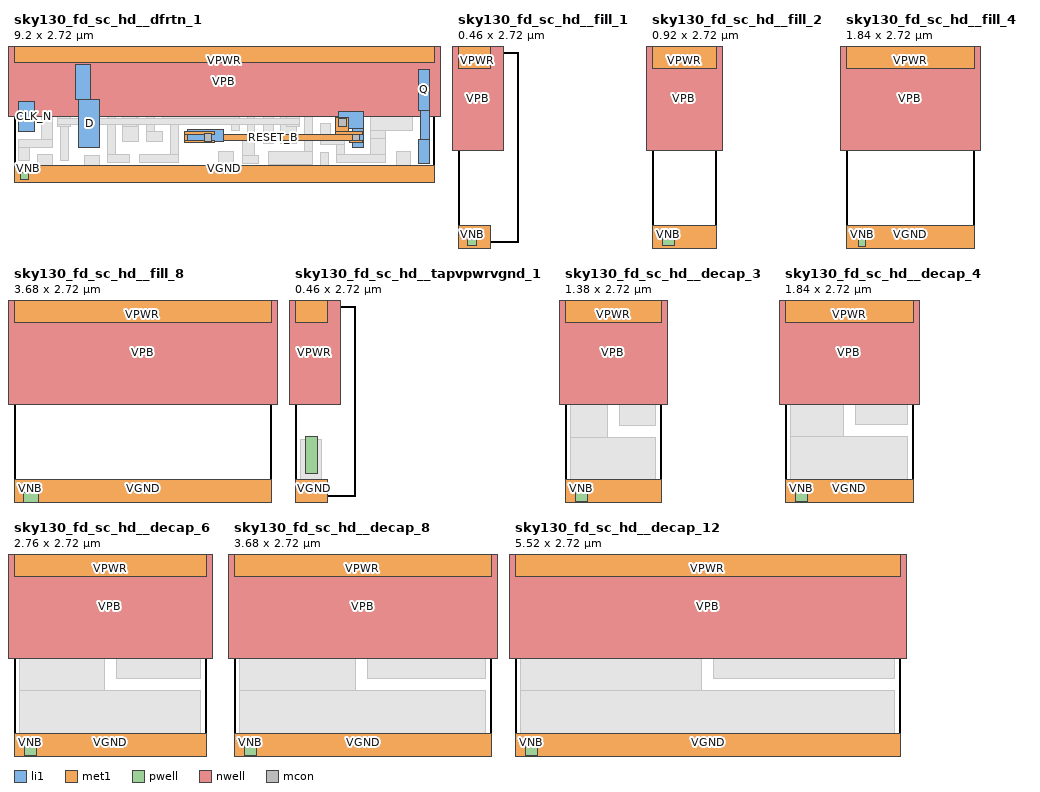
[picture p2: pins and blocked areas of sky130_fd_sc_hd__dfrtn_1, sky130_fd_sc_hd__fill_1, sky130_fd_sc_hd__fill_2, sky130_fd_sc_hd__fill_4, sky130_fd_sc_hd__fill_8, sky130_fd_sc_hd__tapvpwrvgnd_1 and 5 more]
MACRO sky130_fd_sc_hd__dfrtn_1
  CLASS CORE ;
  FOREIGN sky130_fd_sc_hd__dfrtn_1 ;
  ORIGIN  0.000000  0.000000 ;
  SIZE  9.200000 BY  2.720000 ;
  SYMMETRY X Y R90 ;
  SITE unithd ;
  PIN D
    ANTENNAGATEAREA  0.126000 ;
    DIRECTION INPUT ;
    USE SIGNAL ;
    PORT
      LAYER li1 ;
        RECT 1.355000 1.665000 1.680000 2.450000 ;
        RECT 1.415000 0.615000 1.875000 1.665000 ;
    END
  END D
  PIN Q
    ANTENNADIFFAREA  0.429000 ;
    DIRECTION OUTPUT ;
    USE SIGNAL ;
    PORT
      LAYER li1 ;
        RECT 8.855000 0.265000 9.110000 0.795000 ;
        RECT 8.855000 1.445000 9.110000 2.325000 ;
        RECT 8.900000 0.795000 9.110000 1.445000 ;
    END
  END Q
  PIN RESET_B
    ANTENNAGATEAREA  0.252000 ;
    DIRECTION INPUT ;
    USE SIGNAL ;
    PORT
      LAYER li1 ;
        RECT 3.805000 0.765000 4.595000 1.015000 ;
      LAYER mcon ;
        RECT 4.165000 0.765000 4.335000 0.935000 ;
    END
    PORT
      LAYER li1 ;
        RECT 7.105000 1.035000 7.645000 1.405000 ;
        RECT 7.405000 0.635000 7.645000 1.035000 ;
      LAYER mcon ;
        RECT 7.105000 1.080000 7.275000 1.250000 ;
        RECT 7.405000 0.765000 7.575000 0.935000 ;
    END
    PORT
      LAYER met1 ;
        RECT 3.745000 0.735000 4.395000 0.780000 ;
        RECT 3.745000 0.780000 7.635000 0.920000 ;
        RECT 3.745000 0.920000 4.395000 0.965000 ;
        RECT 7.045000 0.920000 7.635000 0.965000 ;
        RECT 7.045000 0.965000 7.335000 1.280000 ;
        RECT 7.345000 0.735000 7.635000 0.780000 ;
    END
  END RESET_B
  PIN CLK_N
    ANTENNAGATEAREA  0.159000 ;
    DIRECTION INPUT ;
    USE CLOCK ;
    PORT
      LAYER li1 ;
        RECT 0.090000 0.975000 0.440000 1.625000 ;
    END
  END CLK_N
  PIN VGND
    DIRECTION INOUT ;
    SHAPE ABUTMENT ;
    USE GROUND ;
    PORT
      LAYER met1 ;
        RECT 0.000000 -0.240000 9.200000 0.240000 ;
    END
  END VGND
  PIN VNB
    DIRECTION INOUT ;
    USE GROUND ;
    PORT
      LAYER pwell ;
        RECT 0.145000 -0.085000 0.315000 0.085000 ;
    END
  END VNB
  PIN VPB
    DIRECTION INOUT ;
    USE POWER ;
    PORT
      LAYER nwell ;
        RECT -0.190000 1.305000 9.390000 2.910000 ;
    END
  END VPB
  PIN VPWR
    DIRECTION INOUT ;
    SHAPE ABUTMENT ;
    USE POWER ;
    PORT
      LAYER met1 ;
        RECT 0.000000 2.480000 9.200000 2.960000 ;
    END
  END VPWR
  OBS
    LAYER li1 ;
      RECT 0.000000 -0.085000 9.200000 0.085000 ;
      RECT 0.000000  2.635000 9.200000 2.805000 ;
      RECT 0.090000  0.345000 0.345000 0.635000 ;
      RECT 0.090000  0.635000 0.840000 0.805000 ;
      RECT 0.090000  1.795000 0.840000 1.965000 ;
      RECT 0.090000  1.965000 0.345000 2.465000 ;
      RECT 0.515000  0.085000 0.845000 0.465000 ;
      RECT 0.515000  2.135000 0.845000 2.635000 ;
      RECT 0.610000  0.805000 0.840000 1.795000 ;
      RECT 1.015000  0.345000 1.185000 2.465000 ;
      RECT 1.545000  0.085000 1.875000 0.445000 ;
      RECT 1.850000  2.175000 2.100000 2.635000 ;
      RECT 2.045000  0.305000 2.540000 0.475000 ;
      RECT 2.045000  0.475000 2.215000 1.835000 ;
      RECT 2.045000  1.835000 2.440000 2.005000 ;
      RECT 2.270000  2.005000 2.440000 2.135000 ;
      RECT 2.270000  2.135000 2.520000 2.465000 ;
      RECT 2.385000  0.765000 2.735000 1.385000 ;
      RECT 2.610000  1.575000 3.075000 1.965000 ;
      RECT 2.735000  2.135000 3.415000 2.465000 ;
      RECT 2.745000  0.305000 3.600000 0.475000 ;
      RECT 2.905000  0.765000 3.260000 0.985000 ;
      RECT 2.905000  0.985000 3.075000 1.575000 ;
      RECT 3.245000  1.185000 4.935000 1.355000 ;
      RECT 3.245000  1.355000 3.415000 2.135000 ;
      RECT 3.430000  0.475000 3.600000 1.185000 ;
      RECT 3.585000  1.865000 4.660000 2.035000 ;
      RECT 3.585000  2.035000 3.755000 2.375000 ;
      RECT 3.775000  1.525000 5.275000 1.695000 ;
      RECT 3.990000  2.205000 4.320000 2.635000 ;
      RECT 4.475000  0.085000 4.805000 0.545000 ;
      RECT 4.490000  2.035000 4.660000 2.375000 ;
      RECT 4.765000  1.005000 4.935000 1.185000 ;
      RECT 4.955000  2.175000 5.325000 2.635000 ;
      RECT 5.015000  0.275000 5.365000 0.445000 ;
      RECT 5.015000  0.445000 5.275000 0.835000 ;
      RECT 5.105000  0.835000 5.275000 1.525000 ;
      RECT 5.105000  1.695000 5.275000 1.835000 ;
      RECT 5.105000  1.835000 5.665000 2.005000 ;
      RECT 5.465000  0.705000 5.675000 1.495000 ;
      RECT 5.465000  1.495000 6.140000 1.655000 ;
      RECT 5.465000  1.655000 6.430000 1.665000 ;
      RECT 5.495000  2.005000 5.665000 2.465000 ;
      RECT 5.585000  0.255000 6.535000 0.535000 ;
      RECT 5.845000  0.705000 6.195000 1.325000 ;
      RECT 5.900000  2.125000 6.770000 2.465000 ;
      RECT 5.970000  1.665000 6.430000 1.955000 ;
      RECT 6.365000  0.535000 6.535000 1.315000 ;
      RECT 6.365000  1.315000 6.770000 1.485000 ;
      RECT 6.600000  1.485000 6.770000 1.575000 ;
      RECT 6.600000  1.575000 7.820000 1.745000 ;
      RECT 6.600000  1.745000 6.770000 2.125000 ;
      RECT 6.705000  0.085000 6.895000 0.525000 ;
      RECT 6.705000  0.695000 7.235000 0.865000 ;
      RECT 6.705000  0.865000 6.925000 1.145000 ;
      RECT 6.940000  2.175000 7.190000 2.635000 ;
      RECT 7.065000  0.295000 8.135000 0.465000 ;
      RECT 7.065000  0.465000 7.235000 0.695000 ;
      RECT 7.360000  1.915000 8.160000 2.085000 ;
      RECT 7.360000  2.085000 7.530000 2.375000 ;
      RECT 7.710000  2.255000 8.040000 2.635000 ;
      RECT 7.815000  0.465000 8.135000 0.820000 ;
      RECT 7.815000  0.820000 8.140000 0.995000 ;
      RECT 7.815000  0.995000 8.730000 1.295000 ;
      RECT 7.990000  1.295000 8.730000 1.325000 ;
      RECT 7.990000  1.325000 8.160000 1.915000 ;
      RECT 8.380000  0.085000 8.685000 0.545000 ;
      RECT 8.380000  1.495000 8.685000 2.635000 ;
    LAYER mcon ;
      RECT 0.145000 -0.085000 0.315000 0.085000 ;
      RECT 0.145000  2.635000 0.315000 2.805000 ;
      RECT 0.605000 -0.085000 0.775000 0.085000 ;
      RECT 0.605000  2.635000 0.775000 2.805000 ;
      RECT 0.655000  1.785000 0.825000 1.955000 ;
      RECT 1.015000  1.105000 1.185000 1.275000 ;
      RECT 1.065000 -0.085000 1.235000 0.085000 ;
      RECT 1.065000  2.635000 1.235000 2.805000 ;
      RECT 1.525000 -0.085000 1.695000 0.085000 ;
      RECT 1.525000  2.635000 1.695000 2.805000 ;
      RECT 1.985000 -0.085000 2.155000 0.085000 ;
      RECT 1.985000  2.635000 2.155000 2.805000 ;
      RECT 2.445000 -0.085000 2.615000 0.085000 ;
      RECT 2.445000  1.105000 2.615000 1.275000 ;
      RECT 2.445000  2.635000 2.615000 2.805000 ;
      RECT 2.905000 -0.085000 3.075000 0.085000 ;
      RECT 2.905000  1.785000 3.075000 1.955000 ;
      RECT 2.905000  2.635000 3.075000 2.805000 ;
      RECT 3.365000 -0.085000 3.535000 0.085000 ;
      RECT 3.365000  2.635000 3.535000 2.805000 ;
      RECT 3.825000 -0.085000 3.995000 0.085000 ;
      RECT 3.825000  2.635000 3.995000 2.805000 ;
      RECT 4.285000 -0.085000 4.455000 0.085000 ;
      RECT 4.285000  2.635000 4.455000 2.805000 ;
      RECT 4.745000 -0.085000 4.915000 0.085000 ;
      RECT 4.745000  2.635000 4.915000 2.805000 ;
      RECT 5.205000 -0.085000 5.375000 0.085000 ;
      RECT 5.205000  2.635000 5.375000 2.805000 ;
      RECT 5.665000 -0.085000 5.835000 0.085000 ;
      RECT 5.665000  2.635000 5.835000 2.805000 ;
      RECT 6.025000  1.105000 6.195000 1.275000 ;
      RECT 6.025000  1.785000 6.195000 1.955000 ;
      RECT 6.125000 -0.085000 6.295000 0.085000 ;
      RECT 6.125000  2.635000 6.295000 2.805000 ;
      RECT 6.585000 -0.085000 6.755000 0.085000 ;
      RECT 6.585000  2.635000 6.755000 2.805000 ;
      RECT 7.045000 -0.085000 7.215000 0.085000 ;
      RECT 7.045000  2.635000 7.215000 2.805000 ;
      RECT 7.505000 -0.085000 7.675000 0.085000 ;
      RECT 7.505000  2.635000 7.675000 2.805000 ;
      RECT 7.965000 -0.085000 8.135000 0.085000 ;
      RECT 7.965000  2.635000 8.135000 2.805000 ;
      RECT 8.425000 -0.085000 8.595000 0.085000 ;
      RECT 8.425000  2.635000 8.595000 2.805000 ;
      RECT 8.885000 -0.085000 9.055000 0.085000 ;
      RECT 8.885000  2.635000 9.055000 2.805000 ;
    LAYER met1 ;
      RECT 0.595000 1.755000 0.885000 1.800000 ;
      RECT 0.595000 1.800000 6.255000 1.940000 ;
      RECT 0.595000 1.940000 0.885000 1.985000 ;
      RECT 0.955000 1.075000 1.245000 1.120000 ;
      RECT 0.955000 1.120000 6.255000 1.260000 ;
      RECT 0.955000 1.260000 1.245000 1.305000 ;
      RECT 2.385000 1.075000 2.675000 1.120000 ;
      RECT 2.385000 1.260000 2.675000 1.305000 ;
      RECT 2.845000 1.755000 3.135000 1.800000 ;
      RECT 2.845000 1.940000 3.135000 1.985000 ;
      RECT 5.965000 1.075000 6.255000 1.120000 ;
      RECT 5.965000 1.260000 6.255000 1.305000 ;
      RECT 5.965000 1.755000 6.255000 1.800000 ;
      RECT 5.965000 1.940000 6.255000 1.985000 ;
  END
END sky130_fd_sc_hd__dfrtn_1

MACRO sky130_fd_sc_hd__fill_1
  CLASS CORE SPACER ;
  FOREIGN sky130_fd_sc_hd__fill_1 ;
  ORIGIN  0.000000  0.000000 ;
  SIZE  0.460000 BY  2.720000 ;
  SYMMETRY X Y R90 ;
  SITE unithd ;
  PIN VGND
    DIRECTION INOUT ;
    SHAPE ABUTMENT ;
    USE GROUND ;
    PORT
      LAYER met1 ;
        RECT 0.000000 -0.240000 0.460000 0.240000 ;
    END
  END VGND
  PIN VNB
    DIRECTION INOUT ;
    USE GROUND ;
    PORT
      LAYER pwell ;
        RECT 0.140000 -0.055000 0.260000 0.055000 ;
    END
  END VNB
  PIN VPB
    DIRECTION INOUT ;
    USE POWER ;
    PORT
      LAYER nwell ;
        RECT -0.190000 1.305000 0.650000 2.910000 ;
    END
  END VPB
  PIN VPWR
    DIRECTION INOUT ;
    SHAPE ABUTMENT ;
    USE POWER ;
    PORT
      LAYER met1 ;
        RECT 0.000000 2.480000 0.460000 2.960000 ;
    END
  END VPWR
  OBS
    LAYER li1 ;
      RECT 0.000000 -0.085000 0.460000 0.085000 ;
      RECT 0.000000  2.635000 0.460000 2.805000 ;
    LAYER mcon ;
      RECT 0.145000 -0.085000 0.315000 0.085000 ;
      RECT 0.145000  2.635000 0.315000 2.805000 ;
  END
END sky130_fd_sc_hd__fill_1

MACRO sky130_fd_sc_hd__fill_2
  CLASS CORE SPACER ;
  FOREIGN sky130_fd_sc_hd__fill_2 ;
  ORIGIN  0.000000  0.000000 ;
  SIZE  0.920000 BY  2.720000 ;
  SYMMETRY X Y R90 ;
  SITE unithd ;
  PIN VGND
    DIRECTION INOUT ;
    SHAPE ABUTMENT ;
    USE GROUND ;
    PORT
      LAYER met1 ;
        RECT 0.000000 -0.240000 0.920000 0.240000 ;
    END
  END VGND
  PIN VNB
    DIRECTION INOUT ;
    USE GROUND ;
    PORT
      LAYER pwell ;
        RECT 0.155000 -0.050000 0.315000 0.060000 ;
    END
  END VNB
  PIN VPB
    DIRECTION INOUT ;
    USE POWER ;
    PORT
      LAYER nwell ;
        RECT -0.190000 1.305000 1.110000 2.910000 ;
    END
  END VPB
  PIN VPWR
    DIRECTION INOUT ;
    SHAPE ABUTMENT ;
    USE POWER ;
    PORT
      LAYER met1 ;
        RECT 0.000000 2.480000 0.920000 2.960000 ;
    END
  END VPWR
  OBS
    LAYER li1 ;
      RECT 0.000000 -0.085000 0.920000 0.085000 ;
      RECT 0.000000  2.635000 0.920000 2.805000 ;
    LAYER mcon ;
      RECT 0.145000 -0.085000 0.315000 0.085000 ;
      RECT 0.145000  2.635000 0.315000 2.805000 ;
      RECT 0.605000 -0.085000 0.775000 0.085000 ;
      RECT 0.605000  2.635000 0.775000 2.805000 ;
  END
END sky130_fd_sc_hd__fill_2

MACRO sky130_fd_sc_hd__fill_4
  CLASS CORE SPACER ;
  FOREIGN sky130_fd_sc_hd__fill_4 ;
  ORIGIN  0.000000  0.000000 ;
  SIZE  1.840000 BY  2.720000 ;
  SYMMETRY X Y R90 ;
  SITE unithd ;
  PIN VGND
    DIRECTION INOUT ;
    SHAPE ABUTMENT ;
    USE GROUND ;
    PORT
      LAYER met1 ;
        RECT 0.000000 -0.240000 1.840000 0.240000 ;
    END
  END VGND
  PIN VNB
    DIRECTION INOUT ;
    USE GROUND ;
    PORT
      LAYER pwell ;
        RECT 0.175000 -0.060000 0.285000 0.060000 ;
    END
  END VNB
  PIN VPB
    DIRECTION INOUT ;
    USE POWER ;
    PORT
      LAYER nwell ;
        RECT -0.190000 1.305000 2.030000 2.910000 ;
    END
  END VPB
  PIN VPWR
    DIRECTION INOUT ;
    SHAPE ABUTMENT ;
    USE POWER ;
    PORT
      LAYER met1 ;
        RECT 0.000000 2.480000 1.840000 2.960000 ;
    END
  END VPWR
  OBS
    LAYER li1 ;
      RECT 0.000000 -0.085000 1.840000 0.085000 ;
      RECT 0.000000  2.635000 1.840000 2.805000 ;
    LAYER mcon ;
      RECT 0.145000 -0.085000 0.315000 0.085000 ;
      RECT 0.145000  2.635000 0.315000 2.805000 ;
      RECT 0.605000 -0.085000 0.775000 0.085000 ;
      RECT 0.605000  2.635000 0.775000 2.805000 ;
      RECT 1.065000 -0.085000 1.235000 0.085000 ;
      RECT 1.065000  2.635000 1.235000 2.805000 ;
      RECT 1.525000 -0.085000 1.695000 0.085000 ;
      RECT 1.525000  2.635000 1.695000 2.805000 ;
  END
END sky130_fd_sc_hd__fill_4

MACRO sky130_fd_sc_hd__fill_8
  CLASS CORE SPACER ;
  FOREIGN sky130_fd_sc_hd__fill_8 ;
  ORIGIN  0.000000  0.000000 ;
  SIZE  3.680000 BY  2.720000 ;
  SYMMETRY X Y R90 ;
  SITE unithd ;
  PIN VGND
    DIRECTION INOUT ;
    SHAPE ABUTMENT ;
    USE GROUND ;
    PORT
      LAYER met1 ;
        RECT 0.000000 -0.240000 3.680000 0.240000 ;
    END
  END VGND
  PIN VNB
    DIRECTION INOUT ;
    USE GROUND ;
    PORT
      LAYER pwell ;
        RECT 0.130000 -0.120000 0.350000 0.050000 ;
    END
  END VNB
  PIN VPB
    DIRECTION INOUT ;
    USE POWER ;
    PORT
      LAYER nwell ;
        RECT -0.190000 1.305000 3.870000 2.910000 ;
    END
  END VPB
  PIN VPWR
    DIRECTION INOUT ;
    SHAPE ABUTMENT ;
    USE POWER ;
    PORT
      LAYER met1 ;
        RECT 0.000000 2.480000 3.680000 2.960000 ;
    END
  END VPWR
  OBS
    LAYER li1 ;
      RECT 0.000000 -0.085000 3.680000 0.085000 ;
      RECT 0.000000  2.635000 3.680000 2.805000 ;
    LAYER mcon ;
      RECT 0.145000 -0.085000 0.315000 0.085000 ;
      RECT 0.145000  2.635000 0.315000 2.805000 ;
      RECT 0.605000 -0.085000 0.775000 0.085000 ;
      RECT 0.605000  2.635000 0.775000 2.805000 ;
      RECT 1.065000 -0.085000 1.235000 0.085000 ;
      RECT 1.065000  2.635000 1.235000 2.805000 ;
      RECT 1.525000 -0.085000 1.695000 0.085000 ;
      RECT 1.525000  2.635000 1.695000 2.805000 ;
      RECT 1.985000 -0.085000 2.155000 0.085000 ;
      RECT 1.985000  2.635000 2.155000 2.805000 ;
      RECT 2.445000 -0.085000 2.615000 0.085000 ;
      RECT 2.445000  2.635000 2.615000 2.805000 ;
      RECT 2.905000 -0.085000 3.075000 0.085000 ;
      RECT 2.905000  2.635000 3.075000 2.805000 ;
      RECT 3.365000 -0.085000 3.535000 0.085000 ;
      RECT 3.365000  2.635000 3.535000 2.805000 ;
  END
END sky130_fd_sc_hd__fill_8

MACRO sky130_fd_sc_hd__tapvpwrvgnd_1
  CLASS CORE WELLTAP ;
  FOREIGN sky130_fd_sc_hd__tapvpwrvgnd_1 ;
  ORIGIN  0.000000  0.000000 ;
  SIZE  0.460000 BY  2.720000 ;
  SYMMETRY X Y R90 ;
  SITE unithd ;
  PIN VGND
    DIRECTION INOUT ;
    SHAPE ABUTMENT ;
    USE GROUND ;
    PORT
      LAYER met1 ;
        RECT 0.000000 -0.240000 0.460000 0.240000 ;
      LAYER pwell ;
        RECT 0.145000 0.320000 0.315000 0.845000 ;
    END
  END VGND
  PIN VPWR
    DIRECTION INOUT ;
    SHAPE ABUTMENT ;
    USE POWER ;
    PORT
      LAYER met1 ;
        RECT 0.000000 2.480000 0.460000 2.960000 ;
      LAYER nwell ;
        RECT -0.190000 1.305000 0.650000 2.910000 ;
    END
  END VPWR
  OBS
    LAYER li1 ;
      RECT 0.000000 -0.085000 0.460000 0.085000 ;
      RECT 0.000000  2.635000 0.460000 2.805000 ;
      RECT 0.085000  0.085000 0.375000 0.810000 ;
      RECT 0.085000  1.470000 0.375000 2.635000 ;
    LAYER mcon ;
      RECT 0.145000 -0.085000 0.315000 0.085000 ;
      RECT 0.145000  2.635000 0.315000 2.805000 ;
  END
END sky130_fd_sc_hd__tapvpwrvgnd_1

MACRO sky130_fd_sc_hd__decap_3
  CLASS CORE ;
  FOREIGN sky130_fd_sc_hd__decap_3 ;
  ORIGIN  0.000000  0.000000 ;
  SIZE  1.380000 BY  2.720000 ;
  SYMMETRY X Y R90 ;
  SITE unithd ;
  PIN VGND
    DIRECTION INOUT ;
    SHAPE ABUTMENT ;
    USE GROUND ;
    PORT
      LAYER met1 ;
        RECT 0.000000 -0.240000 1.380000 0.240000 ;
    END
  END VGND
  PIN VNB
    DIRECTION INOUT ;
    USE GROUND ;
    PORT
      LAYER pwell ;
        RECT 0.145000 -0.085000 0.315000 0.085000 ;
    END
  END VNB
  PIN VPB
    DIRECTION INOUT ;
    USE POWER ;
    PORT
      LAYER nwell ;
        RECT -0.190000 1.305000 1.570000 2.910000 ;
    END
  END VPB
  PIN VPWR
    DIRECTION INOUT ;
    SHAPE ABUTMENT ;
    USE POWER ;
    PORT
      LAYER met1 ;
        RECT 0.000000 2.480000 1.380000 2.960000 ;
    END
  END VPWR
  OBS
    LAYER li1 ;
      RECT 0.000000 -0.085000 1.380000 0.085000 ;
      RECT 0.000000  2.635000 1.380000 2.805000 ;
      RECT 0.085000  0.085000 1.295000 0.835000 ;
      RECT 0.085000  0.835000 0.605000 1.375000 ;
      RECT 0.085000  1.545000 1.295000 2.635000 ;
      RECT 0.775000  1.005000 1.295000 1.545000 ;
    LAYER mcon ;
      RECT 0.145000 -0.085000 0.315000 0.085000 ;
      RECT 0.145000  2.635000 0.315000 2.805000 ;
      RECT 0.605000 -0.085000 0.775000 0.085000 ;
      RECT 0.605000  2.635000 0.775000 2.805000 ;
      RECT 1.065000 -0.085000 1.235000 0.085000 ;
      RECT 1.065000  2.635000 1.235000 2.805000 ;
  END
END sky130_fd_sc_hd__decap_3

MACRO sky130_fd_sc_hd__decap_4
  CLASS CORE ;
  FOREIGN sky130_fd_sc_hd__decap_4 ;
  ORIGIN  0.000000  0.000000 ;
  SIZE  1.840000 BY  2.720000 ;
  SYMMETRY X Y R90 ;
  SITE unithd ;
  PIN VGND
    DIRECTION INOUT ;
    SHAPE ABUTMENT ;
    USE GROUND ;
    PORT
      LAYER met1 ;
        RECT 0.000000 -0.240000 1.840000 0.240000 ;
    END
  END VGND
  PIN VNB
    DIRECTION INOUT ;
    USE GROUND ;
    PORT
      LAYER pwell ;
        RECT 0.145000 -0.085000 0.315000 0.085000 ;
    END
  END VNB
  PIN VPB
    DIRECTION INOUT ;
    USE POWER ;
    PORT
      LAYER nwell ;
        RECT -0.190000 1.305000 2.030000 2.910000 ;
    END
  END VPB
  PIN VPWR
    DIRECTION INOUT ;
    SHAPE ABUTMENT ;
    USE POWER ;
    PORT
      LAYER met1 ;
        RECT 0.000000 2.480000 1.840000 2.960000 ;
    END
  END VPWR
  OBS
    LAYER li1 ;
      RECT 0.000000 -0.085000 1.840000 0.085000 ;
      RECT 0.000000  2.635000 1.840000 2.805000 ;
      RECT 0.085000  0.085000 1.755000 0.855000 ;
      RECT 0.085000  0.855000 0.835000 1.375000 ;
      RECT 0.085000  1.545000 1.755000 2.635000 ;
      RECT 1.005000  1.025000 1.755000 1.545000 ;
    LAYER mcon ;
      RECT 0.145000 -0.085000 0.315000 0.085000 ;
      RECT 0.145000  2.635000 0.315000 2.805000 ;
      RECT 0.605000 -0.085000 0.775000 0.085000 ;
      RECT 0.605000  2.635000 0.775000 2.805000 ;
      RECT 1.065000 -0.085000 1.235000 0.085000 ;
      RECT 1.065000  2.635000 1.235000 2.805000 ;
      RECT 1.525000 -0.085000 1.695000 0.085000 ;
      RECT 1.525000  2.635000 1.695000 2.805000 ;
  END
END sky130_fd_sc_hd__decap_4

MACRO sky130_fd_sc_hd__decap_6
  CLASS CORE ;
  FOREIGN sky130_fd_sc_hd__decap_6 ;
  ORIGIN  0.000000  0.000000 ;
  SIZE  2.760000 BY  2.720000 ;
  SYMMETRY X Y R90 ;
  SITE unithd ;
  PIN VGND
    DIRECTION INOUT ;
    SHAPE ABUTMENT ;
    USE GROUND ;
    PORT
      LAYER met1 ;
        RECT 0.000000 -0.240000 2.760000 0.240000 ;
    END
  END VGND
  PIN VNB
    DIRECTION INOUT ;
    USE GROUND ;
    PORT
      LAYER pwell ;
        RECT 0.145000 -0.085000 0.315000 0.085000 ;
    END
  END VNB
  PIN VPB
    DIRECTION INOUT ;
    USE POWER ;
    PORT
      LAYER nwell ;
        RECT -0.190000 1.305000 2.950000 2.910000 ;
    END
  END VPB
  PIN VPWR
    DIRECTION INOUT ;
    SHAPE ABUTMENT ;
    USE POWER ;
    PORT
      LAYER met1 ;
        RECT 0.000000 2.480000 2.760000 2.960000 ;
    END
  END VPWR
  OBS
    LAYER li1 ;
      RECT 0.000000 -0.085000 2.760000 0.085000 ;
      RECT 0.000000  2.635000 2.760000 2.805000 ;
      RECT 0.085000  0.085000 2.675000 0.855000 ;
      RECT 0.085000  0.855000 1.295000 1.375000 ;
      RECT 0.085000  1.545000 2.675000 2.635000 ;
      RECT 1.465000  1.025000 2.675000 1.545000 ;
    LAYER mcon ;
      RECT 0.145000 -0.085000 0.315000 0.085000 ;
      RECT 0.145000  2.635000 0.315000 2.805000 ;
      RECT 0.605000 -0.085000 0.775000 0.085000 ;
      RECT 0.605000  2.635000 0.775000 2.805000 ;
      RECT 1.065000 -0.085000 1.235000 0.085000 ;
      RECT 1.065000  2.635000 1.235000 2.805000 ;
      RECT 1.525000 -0.085000 1.695000 0.085000 ;
      RECT 1.525000  2.635000 1.695000 2.805000 ;
      RECT 1.985000 -0.085000 2.155000 0.085000 ;
      RECT 1.985000  2.635000 2.155000 2.805000 ;
      RECT 2.445000 -0.085000 2.615000 0.085000 ;
      RECT 2.445000  2.635000 2.615000 2.805000 ;
  END
END sky130_fd_sc_hd__decap_6

MACRO sky130_fd_sc_hd__decap_8
  CLASS CORE ;
  FOREIGN sky130_fd_sc_hd__decap_8 ;
  ORIGIN  0.000000  0.000000 ;
  SIZE  3.680000 BY  2.720000 ;
  SYMMETRY X Y R90 ;
  SITE unithd ;
  PIN VGND
    DIRECTION INOUT ;
    SHAPE ABUTMENT ;
    USE GROUND ;
    PORT
      LAYER met1 ;
        RECT 0.000000 -0.240000 3.680000 0.240000 ;
    END
  END VGND
  PIN VNB
    DIRECTION INOUT ;
    USE GROUND ;
    PORT
      LAYER pwell ;
        RECT 0.145000 -0.085000 0.315000 0.085000 ;
    END
  END VNB
  PIN VPB
    DIRECTION INOUT ;
    USE POWER ;
    PORT
      LAYER nwell ;
        RECT -0.190000 1.305000 3.870000 2.910000 ;
    END
  END VPB
  PIN VPWR
    DIRECTION INOUT ;
    SHAPE ABUTMENT ;
    USE POWER ;
    PORT
      LAYER met1 ;
        RECT 0.000000 2.480000 3.680000 2.960000 ;
    END
  END VPWR
  OBS
    LAYER li1 ;
      RECT 0.000000 -0.085000 3.680000 0.085000 ;
      RECT 0.000000  2.635000 3.680000 2.805000 ;
      RECT 0.085000  0.085000 3.595000 0.855000 ;
      RECT 0.085000  0.855000 1.735000 1.375000 ;
      RECT 0.085000  1.545000 3.595000 2.635000 ;
      RECT 1.905000  1.025000 3.595000 1.545000 ;
    LAYER mcon ;
      RECT 0.145000 -0.085000 0.315000 0.085000 ;
      RECT 0.145000  2.635000 0.315000 2.805000 ;
      RECT 0.605000 -0.085000 0.775000 0.085000 ;
      RECT 0.605000  2.635000 0.775000 2.805000 ;
      RECT 1.065000 -0.085000 1.235000 0.085000 ;
      RECT 1.065000  2.635000 1.235000 2.805000 ;
      RECT 1.525000 -0.085000 1.695000 0.085000 ;
      RECT 1.525000  2.635000 1.695000 2.805000 ;
      RECT 1.985000 -0.085000 2.155000 0.085000 ;
      RECT 1.985000  2.635000 2.155000 2.805000 ;
      RECT 2.445000 -0.085000 2.615000 0.085000 ;
      RECT 2.445000  2.635000 2.615000 2.805000 ;
      RECT 2.905000 -0.085000 3.075000 0.085000 ;
      RECT 2.905000  2.635000 3.075000 2.805000 ;
      RECT 3.365000 -0.085000 3.535000 0.085000 ;
      RECT 3.365000  2.635000 3.535000 2.805000 ;
  END
END sky130_fd_sc_hd__decap_8

MACRO sky130_fd_sc_hd__decap_12
  CLASS CORE ;
  FOREIGN sky130_fd_sc_hd__decap_12 ;
  ORIGIN  0.000000  0.000000 ;
  SIZE  5.520000 BY  2.720000 ;
  SYMMETRY X Y R90 ;
  SITE unithd ;
  PIN VGND
    DIRECTION INOUT ;
    SHAPE ABUTMENT ;
    USE GROUND ;
    PORT
      LAYER met1 ;
        RECT 0.000000 -0.240000 5.520000 0.240000 ;
    END
  END VGND
  PIN VNB
    DIRECTION INOUT ;
    USE GROUND ;
    PORT
      LAYER pwell ;
        RECT 0.145000 -0.085000 0.315000 0.085000 ;
    END
  END VNB
  PIN VPB
    DIRECTION INOUT ;
    USE POWER ;
    PORT
      LAYER nwell ;
        RECT -0.190000 1.305000 5.710000 2.910000 ;
    END
  END VPB
  PIN VPWR
    DIRECTION INOUT ;
    SHAPE ABUTMENT ;
    USE POWER ;
    PORT
      LAYER met1 ;
        RECT 0.000000 2.480000 5.520000 2.960000 ;
    END
  END VPWR
  OBS
    LAYER li1 ;
      RECT 0.000000 -0.085000 5.520000 0.085000 ;
      RECT 0.000000  2.635000 5.520000 2.805000 ;
      RECT 0.085000  0.085000 5.430000 0.855000 ;
      RECT 0.085000  0.855000 2.665000 1.375000 ;
      RECT 0.085000  1.545000 5.430000 2.635000 ;
      RECT 2.835000  1.025000 5.430000 1.545000 ;
    LAYER mcon ;
      RECT 0.145000 -0.085000 0.315000 0.085000 ;
      RECT 0.145000  2.635000 0.315000 2.805000 ;
      RECT 0.605000 -0.085000 0.775000 0.085000 ;
      RECT 0.605000  2.635000 0.775000 2.805000 ;
      RECT 1.065000 -0.085000 1.235000 0.085000 ;
      RECT 1.065000  2.635000 1.235000 2.805000 ;
      RECT 1.525000 -0.085000 1.695000 0.085000 ;
      RECT 1.525000  2.635000 1.695000 2.805000 ;
      RECT 1.985000 -0.085000 2.155000 0.085000 ;
      RECT 1.985000  2.635000 2.155000 2.805000 ;
      RECT 2.445000 -0.085000 2.615000 0.085000 ;
      RECT 2.445000  2.635000 2.615000 2.805000 ;
      RECT 2.905000 -0.085000 3.075000 0.085000 ;
      RECT 2.905000  2.635000 3.075000 2.805000 ;
      RECT 3.365000 -0.085000 3.535000 0.085000 ;
      RECT 3.365000  2.635000 3.535000 2.805000 ;
      RECT 3.825000 -0.085000 3.995000 0.085000 ;
      RECT 3.825000  2.635000 3.995000 2.805000 ;
      RECT 4.285000 -0.085000 4.455000 0.085000 ;
      RECT 4.285000  2.635000 4.455000 2.805000 ;
      RECT 4.745000 -0.085000 4.915000 0.085000 ;
      RECT 4.745000  2.635000 4.915000 2.805000 ;
      RECT 5.205000 -0.085000 5.375000 0.085000 ;
      RECT 5.205000  2.635000 5.375000 2.805000 ;
  END
END sky130_fd_sc_hd__decap_12

END LIBRARY
